VERSION 5.8 ;
BUSBITCHARS "[]" ;
DIVIDERCHAR "/" ;
UNITS
    DATABASE MICRONS 1000 ;
END UNITS

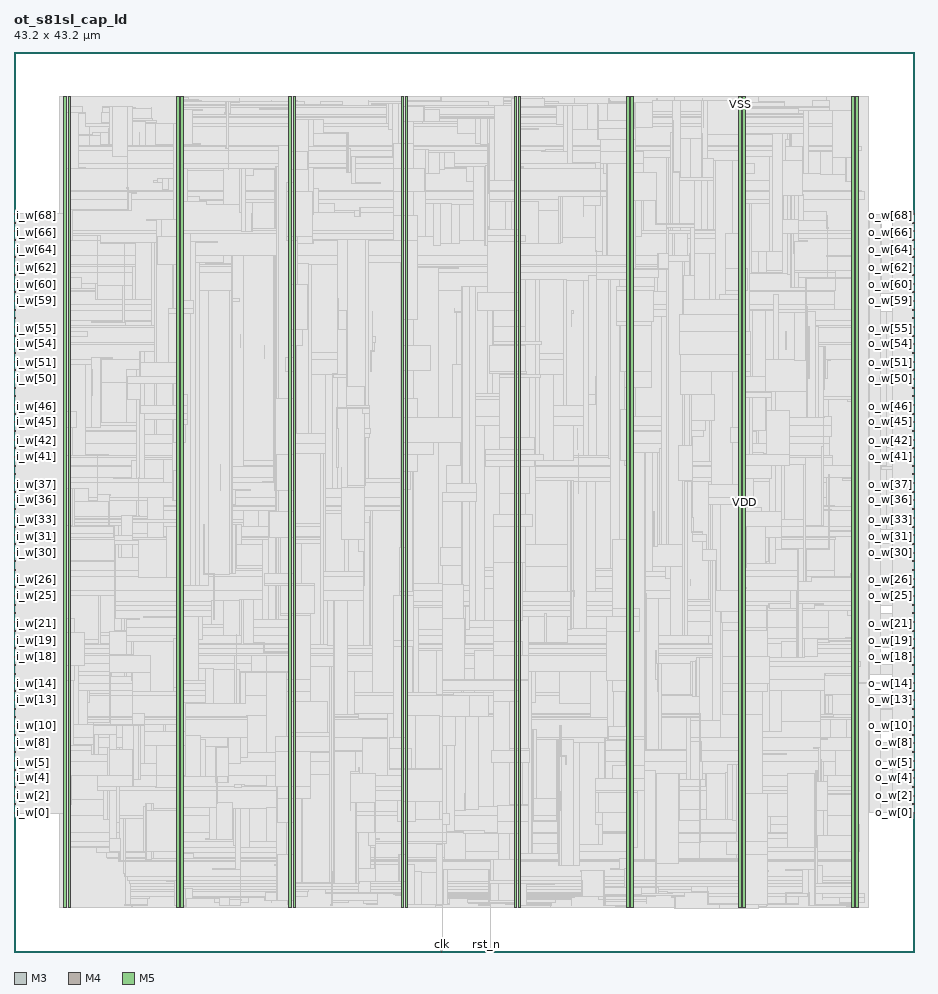
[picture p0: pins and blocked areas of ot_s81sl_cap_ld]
MACRO ot_s81sl_cap_ld
  FOREIGN ot_s81sl_cap_ld 0 0 ;
  CLASS BLOCK ;
  SIZE 43.2 BY 43.2 ;
  PIN clk
    DIRECTION INPUT ;
    USE SIGNAL ;
    PORT
      LAYER M3 ;
        RECT  20.52 0 20.538 0.038 ;
    END
  END clk
  PIN i_w[0]
    DIRECTION INPUT ;
    USE SIGNAL ;
    PORT
      LAYER M4 ;
        RECT  0 6.672 0.084 6.696 ;
    END
  END i_w[0]
  PIN i_w[10]
    DIRECTION INPUT ;
    USE SIGNAL ;
    PORT
      LAYER M4 ;
        RECT  0 10.848 0.084 10.872 ;
    END
  END i_w[10]
  PIN i_w[11]
    DIRECTION INPUT ;
    USE SIGNAL ;
    PORT
      LAYER M4 ;
        RECT  0 11.28 0.084 11.304 ;
    END
  END i_w[11]
  PIN i_w[12]
    DIRECTION INPUT ;
    USE SIGNAL ;
    PORT
      LAYER M4 ;
        RECT  0 11.664 0.084 11.688 ;
    END
  END i_w[12]
  PIN i_w[13]
    DIRECTION INPUT ;
    USE SIGNAL ;
    PORT
      LAYER M4 ;
        RECT  0 12.096 0.084 12.12 ;
    END
  END i_w[13]
  PIN i_w[14]
    DIRECTION INPUT ;
    USE SIGNAL ;
    PORT
      LAYER M4 ;
        RECT  0 12.528 0.084 12.552 ;
    END
  END i_w[14]
  PIN i_w[15]
    DIRECTION INPUT ;
    USE SIGNAL ;
    PORT
      LAYER M4 ;
        RECT  0 12.912 0.084 12.936 ;
    END
  END i_w[15]
  PIN i_w[16]
    DIRECTION INPUT ;
    USE SIGNAL ;
    PORT
      LAYER M4 ;
        RECT  0 13.344 0.084 13.368 ;
    END
  END i_w[16]
  PIN i_w[17]
    DIRECTION INPUT ;
    USE SIGNAL ;
    PORT
      LAYER M4 ;
        RECT  0 13.776 0.084 13.8 ;
    END
  END i_w[17]
  PIN i_w[18]
    DIRECTION INPUT ;
    USE SIGNAL ;
    PORT
      LAYER M4 ;
        RECT  0 14.16 0.084 14.184 ;
    END
  END i_w[18]
  PIN i_w[19]
    DIRECTION INPUT ;
    USE SIGNAL ;
    PORT
      LAYER M4 ;
        RECT  0 14.592 0.084 14.616 ;
    END
  END i_w[19]
  PIN i_w[1]
    DIRECTION INPUT ;
    USE SIGNAL ;
    PORT
      LAYER M4 ;
        RECT  0 7.104 0.084 7.128 ;
    END
  END i_w[1]
  PIN i_w[20]
    DIRECTION INPUT ;
    USE SIGNAL ;
    PORT
      LAYER M4 ;
        RECT  0 15.024 0.084 15.048 ;
    END
  END i_w[20]
  PIN i_w[21]
    DIRECTION INPUT ;
    USE SIGNAL ;
    PORT
      LAYER M4 ;
        RECT  0 15.408 0.084 15.432 ;
    END
  END i_w[21]
  PIN i_w[22]
    DIRECTION INPUT ;
    USE SIGNAL ;
    PORT
      LAYER M4 ;
        RECT  0 15.84 0.084 15.864 ;
    END
  END i_w[22]
  PIN i_w[23]
    DIRECTION INPUT ;
    USE SIGNAL ;
    PORT
      LAYER M4 ;
        RECT  0 16.272 0.084 16.296 ;
    END
  END i_w[23]
  PIN i_w[24]
    DIRECTION INPUT ;
    USE SIGNAL ;
    PORT
      LAYER M4 ;
        RECT  0 16.656 0.084 16.68 ;
    END
  END i_w[24]
  PIN i_w[25]
    DIRECTION INPUT ;
    USE SIGNAL ;
    PORT
      LAYER M4 ;
        RECT  0 17.088 0.084 17.112 ;
    END
  END i_w[25]
  PIN i_w[26]
    DIRECTION INPUT ;
    USE SIGNAL ;
    PORT
      LAYER M4 ;
        RECT  0 17.52 0.084 17.544 ;
    END
  END i_w[26]
  PIN i_w[27]
    DIRECTION INPUT ;
    USE SIGNAL ;
    PORT
      LAYER M4 ;
        RECT  0 17.904 0.084 17.928 ;
    END
  END i_w[27]
  PIN i_w[28]
    DIRECTION INPUT ;
    USE SIGNAL ;
    PORT
      LAYER M4 ;
        RECT  0 18.336 0.084 18.36 ;
    END
  END i_w[28]
  PIN i_w[29]
    DIRECTION INPUT ;
    USE SIGNAL ;
    PORT
      LAYER M4 ;
        RECT  0 18.768 0.084 18.792 ;
    END
  END i_w[29]
  PIN i_w[2]
    DIRECTION INPUT ;
    USE SIGNAL ;
    PORT
      LAYER M4 ;
        RECT  0 7.488 0.084 7.512 ;
    END
  END i_w[2]
  PIN i_w[30]
    DIRECTION INPUT ;
    USE SIGNAL ;
    PORT
      LAYER M4 ;
        RECT  0 19.152 0.084 19.176 ;
    END
  END i_w[30]
  PIN i_w[31]
    DIRECTION INPUT ;
    USE SIGNAL ;
    PORT
      LAYER M4 ;
        RECT  0 19.584 0.084 19.608 ;
    END
  END i_w[31]
  PIN i_w[32]
    DIRECTION INPUT ;
    USE SIGNAL ;
    PORT
      LAYER M4 ;
        RECT  0 20.016 0.084 20.04 ;
    END
  END i_w[32]
  PIN i_w[33]
    DIRECTION INPUT ;
    USE SIGNAL ;
    PORT
      LAYER M4 ;
        RECT  0 20.4 0.084 20.424 ;
    END
  END i_w[33]
  PIN i_w[34]
    DIRECTION INPUT ;
    USE SIGNAL ;
    PORT
      LAYER M4 ;
        RECT  0 20.832 0.084 20.856 ;
    END
  END i_w[34]
  PIN i_w[35]
    DIRECTION INPUT ;
    USE SIGNAL ;
    PORT
      LAYER M4 ;
        RECT  0 21.264 0.084 21.288 ;
    END
  END i_w[35]
  PIN i_w[36]
    DIRECTION INPUT ;
    USE SIGNAL ;
    PORT
      LAYER M4 ;
        RECT  0 21.696 0.084 21.72 ;
    END
  END i_w[36]
  PIN i_w[37]
    DIRECTION INPUT ;
    USE SIGNAL ;
    PORT
      LAYER M4 ;
        RECT  0 22.08 0.084 22.104 ;
    END
  END i_w[37]
  PIN i_w[38]
    DIRECTION INPUT ;
    USE SIGNAL ;
    PORT
      LAYER M4 ;
        RECT  0 22.512 0.084 22.536 ;
    END
  END i_w[38]
  PIN i_w[39]
    DIRECTION INPUT ;
    USE SIGNAL ;
    PORT
      LAYER M4 ;
        RECT  0 22.944 0.084 22.968 ;
    END
  END i_w[39]
  PIN i_w[3]
    DIRECTION INPUT ;
    USE SIGNAL ;
    PORT
      LAYER M4 ;
        RECT  0 7.92 0.084 7.944 ;
    END
  END i_w[3]
  PIN i_w[40]
    DIRECTION INPUT ;
    USE SIGNAL ;
    PORT
      LAYER M4 ;
        RECT  0 23.328 0.084 23.352 ;
    END
  END i_w[40]
  PIN i_w[41]
    DIRECTION INPUT ;
    USE SIGNAL ;
    PORT
      LAYER M4 ;
        RECT  0 23.76 0.084 23.784 ;
    END
  END i_w[41]
  PIN i_w[42]
    DIRECTION INPUT ;
    USE SIGNAL ;
    PORT
      LAYER M4 ;
        RECT  0 24.192 0.084 24.216 ;
    END
  END i_w[42]
  PIN i_w[43]
    DIRECTION INPUT ;
    USE SIGNAL ;
    PORT
      LAYER M4 ;
        RECT  0 24.576 0.084 24.6 ;
    END
  END i_w[43]
  PIN i_w[44]
    DIRECTION INPUT ;
    USE SIGNAL ;
    PORT
      LAYER M4 ;
        RECT  0 25.008 0.084 25.032 ;
    END
  END i_w[44]
  PIN i_w[45]
    DIRECTION INPUT ;
    USE SIGNAL ;
    PORT
      LAYER M4 ;
        RECT  0 25.44 0.084 25.464 ;
    END
  END i_w[45]
  PIN i_w[46]
    DIRECTION INPUT ;
    USE SIGNAL ;
    PORT
      LAYER M4 ;
        RECT  0 25.824 0.084 25.848 ;
    END
  END i_w[46]
  PIN i_w[47]
    DIRECTION INPUT ;
    USE SIGNAL ;
    PORT
      LAYER M4 ;
        RECT  0 26.256 0.084 26.28 ;
    END
  END i_w[47]
  PIN i_w[48]
    DIRECTION INPUT ;
    USE SIGNAL ;
    PORT
      LAYER M4 ;
        RECT  0 26.688 0.084 26.712 ;
    END
  END i_w[48]
  PIN i_w[49]
    DIRECTION INPUT ;
    USE SIGNAL ;
    PORT
      LAYER M4 ;
        RECT  0 27.072 0.084 27.096 ;
    END
  END i_w[49]
  PIN i_w[4]
    DIRECTION INPUT ;
    USE SIGNAL ;
    PORT
      LAYER M4 ;
        RECT  0 8.352 0.084 8.376 ;
    END
  END i_w[4]
  PIN i_w[50]
    DIRECTION INPUT ;
    USE SIGNAL ;
    PORT
      LAYER M4 ;
        RECT  0 27.504 0.084 27.528 ;
    END
  END i_w[50]
  PIN i_w[51]
    DIRECTION INPUT ;
    USE SIGNAL ;
    PORT
      LAYER M4 ;
        RECT  0 27.936 0.084 27.96 ;
    END
  END i_w[51]
  PIN i_w[52]
    DIRECTION INPUT ;
    USE SIGNAL ;
    PORT
      LAYER M4 ;
        RECT  0 28.32 0.084 28.344 ;
    END
  END i_w[52]
  PIN i_w[53]
    DIRECTION INPUT ;
    USE SIGNAL ;
    PORT
      LAYER M4 ;
        RECT  0 28.752 0.084 28.776 ;
    END
  END i_w[53]
  PIN i_w[54]
    DIRECTION INPUT ;
    USE SIGNAL ;
    PORT
      LAYER M4 ;
        RECT  0 29.184 0.084 29.208 ;
    END
  END i_w[54]
  PIN i_w[55]
    DIRECTION INPUT ;
    USE SIGNAL ;
    PORT
      LAYER M4 ;
        RECT  0 29.568 0.084 29.592 ;
    END
  END i_w[55]
  PIN i_w[56]
    DIRECTION INPUT ;
    USE SIGNAL ;
    PORT
      LAYER M4 ;
        RECT  0 30 0.084 30.024 ;
    END
  END i_w[56]
  PIN i_w[57]
    DIRECTION INPUT ;
    USE SIGNAL ;
    PORT
      LAYER M4 ;
        RECT  0 30.432 0.084 30.456 ;
    END
  END i_w[57]
  PIN i_w[58]
    DIRECTION INPUT ;
    USE SIGNAL ;
    PORT
      LAYER M4 ;
        RECT  0 30.816 0.084 30.84 ;
    END
  END i_w[58]
  PIN i_w[59]
    DIRECTION INPUT ;
    USE SIGNAL ;
    PORT
      LAYER M4 ;
        RECT  0 31.248 0.084 31.272 ;
    END
  END i_w[59]
  PIN i_w[5]
    DIRECTION INPUT ;
    USE SIGNAL ;
    PORT
      LAYER M4 ;
        RECT  0 8.736 0.084 8.76 ;
    END
  END i_w[5]
  PIN i_w[60]
    DIRECTION INPUT ;
    USE SIGNAL ;
    PORT
      LAYER M4 ;
        RECT  0 31.68 0.084 31.704 ;
    END
  END i_w[60]
  PIN i_w[61]
    DIRECTION INPUT ;
    USE SIGNAL ;
    PORT
      LAYER M4 ;
        RECT  0 32.064 0.084 32.088 ;
    END
  END i_w[61]
  PIN i_w[62]
    DIRECTION INPUT ;
    USE SIGNAL ;
    PORT
      LAYER M4 ;
        RECT  0 32.496 0.084 32.52 ;
    END
  END i_w[62]
  PIN i_w[63]
    DIRECTION INPUT ;
    USE SIGNAL ;
    PORT
      LAYER M4 ;
        RECT  0 32.928 0.084 32.952 ;
    END
  END i_w[63]
  PIN i_w[64]
    DIRECTION INPUT ;
    USE SIGNAL ;
    PORT
      LAYER M4 ;
        RECT  0 33.36 0.084 33.384 ;
    END
  END i_w[64]
  PIN i_w[65]
    DIRECTION INPUT ;
    USE SIGNAL ;
    PORT
      LAYER M4 ;
        RECT  0 33.744 0.084 33.768 ;
    END
  END i_w[65]
  PIN i_w[66]
    DIRECTION INPUT ;
    USE SIGNAL ;
    PORT
      LAYER M4 ;
        RECT  0 34.176 0.084 34.2 ;
    END
  END i_w[66]
  PIN i_w[67]
    DIRECTION INPUT ;
    USE SIGNAL ;
    PORT
      LAYER M4 ;
        RECT  0 34.608 0.084 34.632 ;
    END
  END i_w[67]
  PIN i_w[68]
    DIRECTION INPUT ;
    USE SIGNAL ;
    PORT
      LAYER M4 ;
        RECT  0 34.992 0.084 35.016 ;
    END
  END i_w[68]
  PIN i_w[69]
    DIRECTION INPUT ;
    USE SIGNAL ;
    PORT
      LAYER M4 ;
        RECT  0 35.424 0.084 35.448 ;
    END
  END i_w[69]
  PIN i_w[6]
    DIRECTION INPUT ;
    USE SIGNAL ;
    PORT
      LAYER M4 ;
        RECT  0 9.168 0.084 9.192 ;
    END
  END i_w[6]
  PIN i_w[7]
    DIRECTION INPUT ;
    USE SIGNAL ;
    PORT
      LAYER M4 ;
        RECT  0 9.6 0.084 9.624 ;
    END
  END i_w[7]
  PIN i_w[8]
    DIRECTION INPUT ;
    USE SIGNAL ;
    PORT
      LAYER M4 ;
        RECT  0 10.032 0.084 10.056 ;
    END
  END i_w[8]
  PIN i_w[9]
    DIRECTION INPUT ;
    USE SIGNAL ;
    PORT
      LAYER M4 ;
        RECT  0 10.416 0.084 10.44 ;
    END
  END i_w[9]
  PIN o_w[0]
    DIRECTION OUTPUT ;
    USE SIGNAL ;
    PORT
      LAYER M4 ;
        RECT  43.116 6.672 43.2 6.696 ;
    END
  END o_w[0]
  PIN o_w[10]
    DIRECTION OUTPUT ;
    USE SIGNAL ;
    PORT
      LAYER M4 ;
        RECT  43.116 10.848 43.2 10.872 ;
    END
  END o_w[10]
  PIN o_w[11]
    DIRECTION OUTPUT ;
    USE SIGNAL ;
    PORT
      LAYER M4 ;
        RECT  43.116 11.28 43.2 11.304 ;
    END
  END o_w[11]
  PIN o_w[12]
    DIRECTION OUTPUT ;
    USE SIGNAL ;
    PORT
      LAYER M4 ;
        RECT  43.116 11.664 43.2 11.688 ;
    END
  END o_w[12]
  PIN o_w[13]
    DIRECTION OUTPUT ;
    USE SIGNAL ;
    PORT
      LAYER M4 ;
        RECT  43.116 12.096 43.2 12.12 ;
    END
  END o_w[13]
  PIN o_w[14]
    DIRECTION OUTPUT ;
    USE SIGNAL ;
    PORT
      LAYER M4 ;
        RECT  43.116 12.528 43.2 12.552 ;
    END
  END o_w[14]
  PIN o_w[15]
    DIRECTION OUTPUT ;
    USE SIGNAL ;
    PORT
      LAYER M4 ;
        RECT  43.116 12.912 43.2 12.936 ;
    END
  END o_w[15]
  PIN o_w[16]
    DIRECTION OUTPUT ;
    USE SIGNAL ;
    PORT
      LAYER M4 ;
        RECT  43.116 13.344 43.2 13.368 ;
    END
  END o_w[16]
  PIN o_w[17]
    DIRECTION OUTPUT ;
    USE SIGNAL ;
    PORT
      LAYER M4 ;
        RECT  43.116 13.776 43.2 13.8 ;
    END
  END o_w[17]
  PIN o_w[18]
    DIRECTION OUTPUT ;
    USE SIGNAL ;
    PORT
      LAYER M4 ;
        RECT  43.116 14.16 43.2 14.184 ;
    END
  END o_w[18]
  PIN o_w[19]
    DIRECTION OUTPUT ;
    USE SIGNAL ;
    PORT
      LAYER M4 ;
        RECT  43.116 14.592 43.2 14.616 ;
    END
  END o_w[19]
  PIN o_w[1]
    DIRECTION OUTPUT ;
    USE SIGNAL ;
    PORT
      LAYER M4 ;
        RECT  43.116 7.104 43.2 7.128 ;
    END
  END o_w[1]
  PIN o_w[20]
    DIRECTION OUTPUT ;
    USE SIGNAL ;
    PORT
      LAYER M4 ;
        RECT  43.116 15.024 43.2 15.048 ;
    END
  END o_w[20]
  PIN o_w[21]
    DIRECTION OUTPUT ;
    USE SIGNAL ;
    PORT
      LAYER M4 ;
        RECT  43.116 15.408 43.2 15.432 ;
    END
  END o_w[21]
  PIN o_w[22]
    DIRECTION OUTPUT ;
    USE SIGNAL ;
    PORT
      LAYER M4 ;
        RECT  43.116 15.84 43.2 15.864 ;
    END
  END o_w[22]
  PIN o_w[23]
    DIRECTION OUTPUT ;
    USE SIGNAL ;
    PORT
      LAYER M4 ;
        RECT  43.116 16.272 43.2 16.296 ;
    END
  END o_w[23]
  PIN o_w[24]
    DIRECTION OUTPUT ;
    USE SIGNAL ;
    PORT
      LAYER M4 ;
        RECT  43.116 16.656 43.2 16.68 ;
    END
  END o_w[24]
  PIN o_w[25]
    DIRECTION OUTPUT ;
    USE SIGNAL ;
    PORT
      LAYER M4 ;
        RECT  43.116 17.088 43.2 17.112 ;
    END
  END o_w[25]
  PIN o_w[26]
    DIRECTION OUTPUT ;
    USE SIGNAL ;
    PORT
      LAYER M4 ;
        RECT  43.116 17.52 43.2 17.544 ;
    END
  END o_w[26]
  PIN o_w[27]
    DIRECTION OUTPUT ;
    USE SIGNAL ;
    PORT
      LAYER M4 ;
        RECT  43.116 17.904 43.2 17.928 ;
    END
  END o_w[27]
  PIN o_w[28]
    DIRECTION OUTPUT ;
    USE SIGNAL ;
    PORT
      LAYER M4 ;
        RECT  43.116 18.336 43.2 18.36 ;
    END
  END o_w[28]
  PIN o_w[29]
    DIRECTION OUTPUT ;
    USE SIGNAL ;
    PORT
      LAYER M4 ;
        RECT  43.116 18.768 43.2 18.792 ;
    END
  END o_w[29]
  PIN o_w[2]
    DIRECTION OUTPUT ;
    USE SIGNAL ;
    PORT
      LAYER M4 ;
        RECT  43.116 7.488 43.2 7.512 ;
    END
  END o_w[2]
  PIN o_w[30]
    DIRECTION OUTPUT ;
    USE SIGNAL ;
    PORT
      LAYER M4 ;
        RECT  43.116 19.152 43.2 19.176 ;
    END
  END o_w[30]
  PIN o_w[31]
    DIRECTION OUTPUT ;
    USE SIGNAL ;
    PORT
      LAYER M4 ;
        RECT  43.116 19.584 43.2 19.608 ;
    END
  END o_w[31]
  PIN o_w[32]
    DIRECTION OUTPUT ;
    USE SIGNAL ;
    PORT
      LAYER M4 ;
        RECT  43.116 20.016 43.2 20.04 ;
    END
  END o_w[32]
  PIN o_w[33]
    DIRECTION OUTPUT ;
    USE SIGNAL ;
    PORT
      LAYER M4 ;
        RECT  43.116 20.4 43.2 20.424 ;
    END
  END o_w[33]
  PIN o_w[34]
    DIRECTION OUTPUT ;
    USE SIGNAL ;
    PORT
      LAYER M4 ;
        RECT  43.116 20.832 43.2 20.856 ;
    END
  END o_w[34]
  PIN o_w[35]
    DIRECTION OUTPUT ;
    USE SIGNAL ;
    PORT
      LAYER M4 ;
        RECT  43.116 21.264 43.2 21.288 ;
    END
  END o_w[35]
  PIN o_w[36]
    DIRECTION OUTPUT ;
    USE SIGNAL ;
    PORT
      LAYER M4 ;
        RECT  43.116 21.696 43.2 21.72 ;
    END
  END o_w[36]
  PIN o_w[37]
    DIRECTION OUTPUT ;
    USE SIGNAL ;
    PORT
      LAYER M4 ;
        RECT  43.116 22.08 43.2 22.104 ;
    END
  END o_w[37]
  PIN o_w[38]
    DIRECTION OUTPUT ;
    USE SIGNAL ;
    PORT
      LAYER M4 ;
        RECT  43.116 22.512 43.2 22.536 ;
    END
  END o_w[38]
  PIN o_w[39]
    DIRECTION OUTPUT ;
    USE SIGNAL ;
    PORT
      LAYER M4 ;
        RECT  43.116 22.944 43.2 22.968 ;
    END
  END o_w[39]
  PIN o_w[3]
    DIRECTION OUTPUT ;
    USE SIGNAL ;
    PORT
      LAYER M4 ;
        RECT  43.116 7.92 43.2 7.944 ;
    END
  END o_w[3]
  PIN o_w[40]
    DIRECTION OUTPUT ;
    USE SIGNAL ;
    PORT
      LAYER M4 ;
        RECT  43.116 23.328 43.2 23.352 ;
    END
  END o_w[40]
  PIN o_w[41]
    DIRECTION OUTPUT ;
    USE SIGNAL ;
    PORT
      LAYER M4 ;
        RECT  43.116 23.76 43.2 23.784 ;
    END
  END o_w[41]
  PIN o_w[42]
    DIRECTION OUTPUT ;
    USE SIGNAL ;
    PORT
      LAYER M4 ;
        RECT  43.116 24.192 43.2 24.216 ;
    END
  END o_w[42]
  PIN o_w[43]
    DIRECTION OUTPUT ;
    USE SIGNAL ;
    PORT
      LAYER M4 ;
        RECT  43.116 24.576 43.2 24.6 ;
    END
  END o_w[43]
  PIN o_w[44]
    DIRECTION OUTPUT ;
    USE SIGNAL ;
    PORT
      LAYER M4 ;
        RECT  43.116 25.008 43.2 25.032 ;
    END
  END o_w[44]
  PIN o_w[45]
    DIRECTION OUTPUT ;
    USE SIGNAL ;
    PORT
      LAYER M4 ;
        RECT  43.116 25.44 43.2 25.464 ;
    END
  END o_w[45]
  PIN o_w[46]
    DIRECTION OUTPUT ;
    USE SIGNAL ;
    PORT
      LAYER M4 ;
        RECT  43.116 25.824 43.2 25.848 ;
    END
  END o_w[46]
  PIN o_w[47]
    DIRECTION OUTPUT ;
    USE SIGNAL ;
    PORT
      LAYER M4 ;
        RECT  43.116 26.256 43.2 26.28 ;
    END
  END o_w[47]
  PIN o_w[48]
    DIRECTION OUTPUT ;
    USE SIGNAL ;
    PORT
      LAYER M4 ;
        RECT  43.116 26.688 43.2 26.712 ;
    END
  END o_w[48]
  PIN o_w[49]
    DIRECTION OUTPUT ;
    USE SIGNAL ;
    PORT
      LAYER M4 ;
        RECT  43.116 27.072 43.2 27.096 ;
    END
  END o_w[49]
  PIN o_w[4]
    DIRECTION OUTPUT ;
    USE SIGNAL ;
    PORT
      LAYER M4 ;
        RECT  43.116 8.352 43.2 8.376 ;
    END
  END o_w[4]
  PIN o_w[50]
    DIRECTION OUTPUT ;
    USE SIGNAL ;
    PORT
      LAYER M4 ;
        RECT  43.116 27.504 43.2 27.528 ;
    END
  END o_w[50]
  PIN o_w[51]
    DIRECTION OUTPUT ;
    USE SIGNAL ;
    PORT
      LAYER M4 ;
        RECT  43.116 27.936 43.2 27.96 ;
    END
  END o_w[51]
  PIN o_w[52]
    DIRECTION OUTPUT ;
    USE SIGNAL ;
    PORT
      LAYER M4 ;
        RECT  43.116 28.32 43.2 28.344 ;
    END
  END o_w[52]
  PIN o_w[53]
    DIRECTION OUTPUT ;
    USE SIGNAL ;
    PORT
      LAYER M4 ;
        RECT  43.116 28.752 43.2 28.776 ;
    END
  END o_w[53]
  PIN o_w[54]
    DIRECTION OUTPUT ;
    USE SIGNAL ;
    PORT
      LAYER M4 ;
        RECT  43.116 29.184 43.2 29.208 ;
    END
  END o_w[54]
  PIN o_w[55]
    DIRECTION OUTPUT ;
    USE SIGNAL ;
    PORT
      LAYER M4 ;
        RECT  43.116 29.568 43.2 29.592 ;
    END
  END o_w[55]
  PIN o_w[56]
    DIRECTION OUTPUT ;
    USE SIGNAL ;
    PORT
      LAYER M4 ;
        RECT  43.116 30 43.2 30.024 ;
    END
  END o_w[56]
  PIN o_w[57]
    DIRECTION OUTPUT ;
    USE SIGNAL ;
    PORT
      LAYER M4 ;
        RECT  43.116 30.432 43.2 30.456 ;
    END
  END o_w[57]
  PIN o_w[58]
    DIRECTION OUTPUT ;
    USE SIGNAL ;
    PORT
      LAYER M4 ;
        RECT  43.116 30.816 43.2 30.84 ;
    END
  END o_w[58]
  PIN o_w[59]
    DIRECTION OUTPUT ;
    USE SIGNAL ;
    PORT
      LAYER M4 ;
        RECT  43.116 31.248 43.2 31.272 ;
    END
  END o_w[59]
  PIN o_w[5]
    DIRECTION OUTPUT ;
    USE SIGNAL ;
    PORT
      LAYER M4 ;
        RECT  43.116 8.736 43.2 8.76 ;
    END
  END o_w[5]
  PIN o_w[60]
    DIRECTION OUTPUT ;
    USE SIGNAL ;
    PORT
      LAYER M4 ;
        RECT  43.116 31.68 43.2 31.704 ;
    END
  END o_w[60]
  PIN o_w[61]
    DIRECTION OUTPUT ;
    USE SIGNAL ;
    PORT
      LAYER M4 ;
        RECT  43.116 32.064 43.2 32.088 ;
    END
  END o_w[61]
  PIN o_w[62]
    DIRECTION OUTPUT ;
    USE SIGNAL ;
    PORT
      LAYER M4 ;
        RECT  43.116 32.496 43.2 32.52 ;
    END
  END o_w[62]
  PIN o_w[63]
    DIRECTION OUTPUT ;
    USE SIGNAL ;
    PORT
      LAYER M4 ;
        RECT  43.116 32.928 43.2 32.952 ;
    END
  END o_w[63]
  PIN o_w[64]
    DIRECTION OUTPUT ;
    USE SIGNAL ;
    PORT
      LAYER M4 ;
        RECT  43.116 33.36 43.2 33.384 ;
    END
  END o_w[64]
  PIN o_w[65]
    DIRECTION OUTPUT ;
    USE SIGNAL ;
    PORT
      LAYER M4 ;
        RECT  43.116 33.744 43.2 33.768 ;
    END
  END o_w[65]
  PIN o_w[66]
    DIRECTION OUTPUT ;
    USE SIGNAL ;
    PORT
      LAYER M4 ;
        RECT  43.116 34.176 43.2 34.2 ;
    END
  END o_w[66]
  PIN o_w[67]
    DIRECTION OUTPUT ;
    USE SIGNAL ;
    PORT
      LAYER M4 ;
        RECT  43.116 34.608 43.2 34.632 ;
    END
  END o_w[67]
  PIN o_w[68]
    DIRECTION OUTPUT ;
    USE SIGNAL ;
    PORT
      LAYER M4 ;
        RECT  43.116 34.992 43.2 35.016 ;
    END
  END o_w[68]
  PIN o_w[69]
    DIRECTION OUTPUT ;
    USE SIGNAL ;
    PORT
      LAYER M4 ;
        RECT  43.116 35.424 43.2 35.448 ;
    END
  END o_w[69]
  PIN o_w[6]
    DIRECTION OUTPUT ;
    USE SIGNAL ;
    PORT
      LAYER M4 ;
        RECT  43.116 9.168 43.2 9.192 ;
    END
  END o_w[6]
  PIN o_w[7]
    DIRECTION OUTPUT ;
    USE SIGNAL ;
    PORT
      LAYER M4 ;
        RECT  43.116 9.6 43.2 9.624 ;
    END
  END o_w[7]
  PIN o_w[8]
    DIRECTION OUTPUT ;
    USE SIGNAL ;
    PORT
      LAYER M4 ;
        RECT  43.116 10.032 43.2 10.056 ;
    END
  END o_w[8]
  PIN o_w[9]
    DIRECTION OUTPUT ;
    USE SIGNAL ;
    PORT
      LAYER M4 ;
        RECT  43.116 10.416 43.2 10.44 ;
    END
  END o_w[9]
  PIN rst_n
    DIRECTION INPUT ;
    USE SIGNAL ;
    PORT
      LAYER M3 ;
        RECT  22.68 0 22.698 0.038 ;
    END
  END rst_n
  PIN VDD
    DIRECTION INOUT ;
    USE POWER ;
    PORT
      LAYER M5 ;
        RECT  40.392 2.151 40.512 41.049 ;
        RECT  34.992 2.151 35.112 41.049 ;
        RECT  29.592 2.151 29.712 41.049 ;
        RECT  24.192 2.151 24.312 41.049 ;
        RECT  18.792 2.151 18.912 41.049 ;
        RECT  13.392 2.151 13.512 41.049 ;
        RECT  7.992 2.151 8.112 41.049 ;
        RECT  2.592 2.151 2.712 41.049 ;
    END
  END VDD
  PIN VSS
    DIRECTION INOUT ;
    USE GROUND ;
    PORT
      LAYER M5 ;
        RECT  40.2 2.137 40.32 41.063 ;
        RECT  34.8 2.137 34.92 41.063 ;
        RECT  29.4 2.137 29.52 41.063 ;
        RECT  24 2.137 24.12 41.063 ;
        RECT  18.6 2.137 18.72 41.063 ;
        RECT  13.2 2.137 13.32 41.063 ;
        RECT  7.8 2.137 7.92 41.063 ;
        RECT  2.4 2.137 2.52 41.063 ;
    END
  END VSS
  OBS
    LAYER RVTN ;
     RECT  2.16 2.16 41.04 2.295 ;
     RECT  2.16 2.565 41.04 2.835 ;
     RECT  2.16 3.105 41.04 3.375 ;
     RECT  2.16 3.645 41.04 3.915 ;
     RECT  2.16 4.185 41.04 4.455 ;
     RECT  2.16 4.725 41.04 4.995 ;
     RECT  2.16 5.265 41.04 5.535 ;
     RECT  2.16 5.805 41.04 6.075 ;
     RECT  2.16 6.345 41.04 6.615 ;
     RECT  2.16 6.885 41.04 7.155 ;
     RECT  2.16 7.425 41.04 7.695 ;
     RECT  2.16 7.965 41.04 8.235 ;
     RECT  2.16 8.505 41.04 8.775 ;
     RECT  2.16 9.045 41.04 9.315 ;
     RECT  2.16 9.585 41.04 9.855 ;
     RECT  2.16 10.125 41.04 10.395 ;
     RECT  2.16 10.665 41.04 10.935 ;
     RECT  2.16 11.205 41.04 11.475 ;
     RECT  2.16 11.745 41.04 12.015 ;
     RECT  2.16 12.285 41.04 12.555 ;
     RECT  2.16 12.825 41.04 13.095 ;
     RECT  2.16 13.365 41.04 13.635 ;
     RECT  2.16 13.905 41.04 14.175 ;
     RECT  2.16 14.445 41.04 14.715 ;
     RECT  2.16 14.985 41.04 15.255 ;
     RECT  2.16 15.525 41.04 15.795 ;
     RECT  2.16 16.065 41.04 16.335 ;
     RECT  2.16 16.605 41.04 16.875 ;
     RECT  2.16 17.145 41.04 17.415 ;
     RECT  2.16 17.685 41.04 17.955 ;
     RECT  2.16 18.225 41.04 18.495 ;
     RECT  2.16 18.765 41.04 19.035 ;
     RECT  2.16 19.305 41.04 19.575 ;
     RECT  2.16 19.845 41.04 20.115 ;
     RECT  2.16 20.385 41.04 20.655 ;
     RECT  2.16 20.925 41.04 21.195 ;
     RECT  2.16 21.465 41.04 21.735 ;
     RECT  2.16 22.005 41.04 22.275 ;
     RECT  2.16 22.545 41.04 22.815 ;
     RECT  2.16 23.085 41.04 23.355 ;
     RECT  2.16 23.625 41.04 23.895 ;
     RECT  2.16 24.165 41.04 24.435 ;
     RECT  2.16 24.705 41.04 24.975 ;
     RECT  2.16 25.245 41.04 25.515 ;
     RECT  2.16 25.785 41.04 26.055 ;
     RECT  2.16 26.325 41.04 26.595 ;
     RECT  2.16 26.865 41.04 27.135 ;
     RECT  2.16 27.405 41.04 27.675 ;
     RECT  2.16 27.945 41.04 28.215 ;
     RECT  2.16 28.485 41.04 28.755 ;
     RECT  2.16 29.025 41.04 29.295 ;
     RECT  2.16 29.565 41.04 29.835 ;
     RECT  2.16 30.105 41.04 30.375 ;
     RECT  2.16 30.645 41.04 30.915 ;
     RECT  2.16 31.185 41.04 31.455 ;
     RECT  2.16 31.725 41.04 31.995 ;
     RECT  2.16 32.265 41.04 32.535 ;
     RECT  2.16 32.805 41.04 33.075 ;
     RECT  2.16 33.345 41.04 33.615 ;
     RECT  2.16 33.885 41.04 34.155 ;
     RECT  2.16 34.425 41.04 34.695 ;
     RECT  2.16 34.965 41.04 35.235 ;
     RECT  2.16 35.505 41.04 35.775 ;
     RECT  2.16 36.045 41.04 36.315 ;
     RECT  2.16 36.585 41.04 36.855 ;
     RECT  2.16 37.125 41.04 37.395 ;
     RECT  2.16 37.665 41.04 37.935 ;
     RECT  2.16 38.205 41.04 38.475 ;
     RECT  2.16 38.745 41.04 39.015 ;
     RECT  2.16 39.285 41.04 39.555 ;
     RECT  2.16 39.825 41.04 40.095 ;
     RECT  2.16 40.365 41.04 40.635 ;
     RECT  2.16 40.905 41.04 41.04 ;
    LAYER RVTP ;
     RECT  2.16 2.295 41.04 2.565 ;
     RECT  2.16 2.835 41.04 3.105 ;
     RECT  2.16 3.375 41.04 3.645 ;
     RECT  2.16 3.915 41.04 4.185 ;
     RECT  2.16 4.455 41.04 4.725 ;
     RECT  2.16 4.995 41.04 5.265 ;
     RECT  2.16 5.535 41.04 5.805 ;
     RECT  2.16 6.075 41.04 6.345 ;
     RECT  2.16 6.615 41.04 6.885 ;
     RECT  2.16 7.155 41.04 7.425 ;
     RECT  2.16 7.695 41.04 7.965 ;
     RECT  2.16 8.235 41.04 8.505 ;
     RECT  2.16 8.775 41.04 9.045 ;
     RECT  2.16 9.315 41.04 9.585 ;
     RECT  2.16 9.855 41.04 10.125 ;
     RECT  2.16 10.395 41.04 10.665 ;
     RECT  2.16 10.935 41.04 11.205 ;
     RECT  2.16 11.475 41.04 11.745 ;
     RECT  2.16 12.015 41.04 12.285 ;
     RECT  2.16 12.555 41.04 12.825 ;
     RECT  2.16 13.095 41.04 13.365 ;
     RECT  2.16 13.635 41.04 13.905 ;
     RECT  2.16 14.175 41.04 14.445 ;
     RECT  2.16 14.715 41.04 14.985 ;
     RECT  2.16 15.255 41.04 15.525 ;
     RECT  2.16 15.795 41.04 16.065 ;
     RECT  2.16 16.335 41.04 16.605 ;
     RECT  2.16 16.875 41.04 17.145 ;
     RECT  2.16 17.415 41.04 17.685 ;
     RECT  2.16 17.955 41.04 18.225 ;
     RECT  2.16 18.495 41.04 18.765 ;
     RECT  2.16 19.035 41.04 19.305 ;
     RECT  2.16 19.575 41.04 19.845 ;
     RECT  2.16 20.115 41.04 20.385 ;
     RECT  2.16 20.655 41.04 20.925 ;
     RECT  2.16 21.195 41.04 21.465 ;
     RECT  2.16 21.735 41.04 22.005 ;
     RECT  2.16 22.275 41.04 22.545 ;
     RECT  2.16 22.815 41.04 23.085 ;
     RECT  2.16 23.355 41.04 23.625 ;
     RECT  2.16 23.895 41.04 24.165 ;
     RECT  2.16 24.435 41.04 24.705 ;
     RECT  2.16 24.975 41.04 25.245 ;
     RECT  2.16 25.515 41.04 25.785 ;
     RECT  2.16 26.055 41.04 26.325 ;
     RECT  2.16 26.595 41.04 26.865 ;
     RECT  2.16 27.135 41.04 27.405 ;
     RECT  2.16 27.675 41.04 27.945 ;
     RECT  2.16 28.215 41.04 28.485 ;
     RECT  2.16 28.755 41.04 29.025 ;
     RECT  2.16 29.295 41.04 29.565 ;
     RECT  2.16 29.835 41.04 30.105 ;
     RECT  2.16 30.375 41.04 30.645 ;
     RECT  2.16 30.915 41.04 31.185 ;
     RECT  2.16 31.455 41.04 31.725 ;
     RECT  2.16 31.995 41.04 32.265 ;
     RECT  2.16 32.535 41.04 32.805 ;
     RECT  2.16 33.075 41.04 33.345 ;
     RECT  2.16 33.615 41.04 33.885 ;
     RECT  2.16 34.155 41.04 34.425 ;
     RECT  2.16 34.695 41.04 34.965 ;
     RECT  2.16 35.235 41.04 35.505 ;
     RECT  2.16 35.775 41.04 36.045 ;
     RECT  2.16 36.315 41.04 36.585 ;
     RECT  2.16 36.855 41.04 37.125 ;
     RECT  2.16 37.395 41.04 37.665 ;
     RECT  2.16 37.935 41.04 38.205 ;
     RECT  2.16 38.475 41.04 38.745 ;
     RECT  2.16 39.015 41.04 39.285 ;
     RECT  2.16 39.555 41.04 39.825 ;
     RECT  2.16 40.095 41.04 40.365 ;
     RECT  2.16 40.635 41.04 40.905 ;
    LAYER M1 ;
     RECT  2.16 2.151 41.04 41.049 ;
    LAYER M2 ;
     RECT  0.103 12.528 2.16 12.546 ;
     RECT  0.103 17.082 2.16 17.1 ;
     RECT  0.103 24.48 2.16 24.498 ;
     RECT  0.103 32.472 2.16 32.49 ;
     RECT  22.675 0.036 22.883 0.054 ;
     RECT  2.16 2.151 31.711 41.049 ;
     RECT  31.711 2.106 35.735 41.049 ;
     RECT  35.735 2.151 41.04 41.049 ;
     RECT  41.04 6.696 41.063 35.424 ;
     RECT  41.063 6.696 41.603 12.384 ;
     RECT  41.063 13.338 41.603 35.424 ;
     RECT  41.603 18.126 41.639 18.684 ;
     RECT  41.603 31.626 41.639 35.424 ;
     RECT  41.603 20.286 41.891 30.744 ;
     RECT  41.603 6.696 42.179 8.766 ;
     RECT  41.603 9.756 42.179 9.774 ;
     RECT  41.603 10.566 42.179 12.384 ;
     RECT  41.603 13.338 42.179 13.824 ;
     RECT  41.603 14.616 42.179 16.254 ;
     RECT  41.639 18.126 42.179 18.144 ;
     RECT  41.891 20.286 42.179 23.814 ;
     RECT  41.891 24.606 42.179 30.744 ;
     RECT  41.639 31.626 42.179 34.344 ;
     RECT  41.639 35.136 42.179 35.424 ;
     RECT  42.179 11.916 42.215 12.384 ;
     RECT  42.179 30.726 42.215 30.744 ;
     RECT  42.215 12.366 43.115 12.384 ;
     RECT  42.179 15.336 43.115 15.354 ;
     RECT  41.603 17.046 43.115 17.064 ;
     RECT  42.179 26.226 43.115 26.244 ;
     RECT  42.179 27.756 43.115 27.774 ;
     RECT  42.179 32.436 43.115 32.454 ;
     RECT  42.179 34.326 43.115 34.344 ;
    LAYER M3 ;
     RECT  22.68 0.012 22.698 0.031 ;
     RECT  22.68 0.031 22.878 0.059 ;
     RECT  20.52 0.012 20.538 0.125 ;
     RECT  7.815 2.143 7.905 2.191 ;
     RECT  29.415 2.143 29.505 2.191 ;
     RECT  35.712 2.101 35.73 2.191 ;
     RECT  40.215 2.143 40.305 2.191 ;
     RECT  5.652 2.191 5.67 2.227 ;
     RECT  7.815 2.191 8.298 2.227 ;
     RECT  20.232 2.191 20.25 2.227 ;
     RECT  28.872 2.191 29.505 2.227 ;
     RECT  5.652 2.227 6.39 2.251 ;
     RECT  22.86 0.059 22.878 2.251 ;
     RECT  24.015 2.143 24.105 2.251 ;
     RECT  25.74 2.191 25.758 2.251 ;
     RECT  39.96 2.191 40.305 2.251 ;
     RECT  9.864 2.227 9.882 2.263 ;
     RECT  20.232 2.227 20.538 2.263 ;
     RECT  24.015 2.251 24.57 2.263 ;
     RECT  25.74 2.251 25.794 2.263 ;
     RECT  5.472 2.251 6.39 2.291 ;
     RECT  9.864 2.263 10.278 2.299 ;
     RECT  13.215 2.143 13.305 2.299 ;
     RECT  18.615 2.143 18.705 2.299 ;
     RECT  19.836 2.263 20.538 2.299 ;
     RECT  24.015 2.263 25.794 2.299 ;
     RECT  33.84 2.101 33.858 2.299 ;
     RECT  34.815 2.143 34.905 2.299 ;
     RECT  35.712 2.191 36.126 2.299 ;
     RECT  37.296 2.263 37.314 2.299 ;
     RECT  16.92 2.263 17.442 2.335 ;
     RECT  22.32 2.251 22.878 2.335 ;
     RECT  23.616 2.299 25.794 2.335 ;
     RECT  33.3 2.299 33.858 2.335 ;
     RECT  34.596 2.299 34.905 2.335 ;
     RECT  35.712 2.299 37.674 2.335 ;
     RECT  39.6 2.251 40.305 2.335 ;
     RECT  9.864 2.299 10.89 2.371 ;
     RECT  15.264 2.227 15.282 2.371 ;
     RECT  21.816 2.335 25.794 2.371 ;
     RECT  39.6 2.335 40.374 2.371 ;
     RECT  2.415 2.143 2.505 2.413 ;
     RECT  13.14 2.299 13.305 2.413 ;
     RECT  28.332 2.227 29.505 2.413 ;
     RECT  30.348 2.335 30.366 2.413 ;
     RECT  15.264 2.371 16.038 2.461 ;
     RECT  16.776 2.335 17.442 2.461 ;
     RECT  12.348 2.371 12.366 2.491 ;
     RECT  21.78 2.371 25.974 2.497 ;
     RECT  26.748 2.227 26.766 2.497 ;
     RECT  28.332 2.413 30.366 2.533 ;
     RECT  5.58 2.291 6.39 2.569 ;
     RECT  18.615 2.299 20.898 2.569 ;
     RECT  21.78 2.497 26.766 2.569 ;
     RECT  7.704 2.227 8.298 2.605 ;
     RECT  9.648 2.371 11.25 2.605 ;
     RECT  12.024 2.491 12.366 2.605 ;
     RECT  18.615 2.569 26.766 2.605 ;
     RECT  31.716 2.101 31.734 2.605 ;
     RECT  38.808 2.533 38.826 2.605 ;
     RECT  39.6 2.371 40.842 2.605 ;
     RECT  5.58 2.569 6.498 2.641 ;
     RECT  7.704 2.605 8.55 2.641 ;
     RECT  9.648 2.605 12.366 2.641 ;
     RECT  13.14 2.413 13.497 2.641 ;
     RECT  18.615 2.605 26.91 2.641 ;
     RECT  28.08 2.533 30.366 2.641 ;
     RECT  31.572 2.605 31.734 2.641 ;
     RECT  33.3 2.335 37.674 2.641 ;
     RECT  18.615 2.641 27.342 2.731 ;
     RECT  28.08 2.641 30.798 2.731 ;
     RECT  31.572 2.641 32.166 2.731 ;
     RECT  18.324 2.731 27.342 2.767 ;
     RECT  38.808 2.605 40.842 2.795 ;
     RECT  15.264 2.461 17.442 2.803 ;
     RECT  18.216 2.767 27.342 2.803 ;
     RECT  33.3 2.641 38.07 2.827 ;
     RECT  38.808 2.795 40.497 2.827 ;
     RECT  14.94 2.803 27.342 2.875 ;
     RECT  28.08 2.731 32.166 2.875 ;
     RECT  5.58 2.641 14.094 2.911 ;
     RECT  5.58 2.911 14.13 3.001 ;
     RECT  14.94 2.875 32.526 3.001 ;
     RECT  5.58 3.001 32.526 3.145 ;
     RECT  33.3 2.827 40.497 3.145 ;
     RECT  5.58 3.145 40.497 3.307 ;
     RECT  5.544 3.307 40.497 3.451 ;
     RECT  5.436 3.451 40.497 3.613 ;
     RECT  5.292 3.613 40.497 4.363 ;
     RECT  5.004 4.363 40.497 4.415 ;
     RECT  14.94 4.415 40.497 4.451 ;
     RECT  5.004 4.415 14.166 4.495 ;
     RECT  4.464 4.495 14.166 4.531 ;
     RECT  14.94 4.451 20.682 4.541 ;
     RECT  4.428 4.531 14.166 4.765 ;
     RECT  21.672 4.451 40.497 4.801 ;
     RECT  2.415 2.413 2.697 5.035 ;
     RECT  3.96 4.765 14.166 5.035 ;
     RECT  15.156 4.541 20.682 5.197 ;
     RECT  2.415 5.035 14.166 5.305 ;
     RECT  15.156 5.197 20.754 5.305 ;
     RECT  21.672 4.801 40.59 5.701 ;
     RECT  2.415 5.305 20.754 5.737 ;
     RECT  21.6 5.701 40.59 5.737 ;
     RECT  2.415 5.737 40.59 5.741 ;
     RECT  36.324 5.741 40.59 6.143 ;
     RECT  2.415 5.741 35.442 6.547 ;
     RECT  36.324 6.143 40.497 6.547 ;
     RECT  0.108 7.483 0.126 7.661 ;
     RECT  2.415 6.547 40.497 7.735 ;
     RECT  2.304 7.735 40.497 7.949 ;
     RECT  2.415 7.949 40.497 8.465 ;
     RECT  42.156 6.667 42.174 8.771 ;
     RECT  2.415 8.465 39.438 9.163 ;
     RECT  41.58 9.163 41.598 9.239 ;
     RECT  2.304 9.163 39.438 9.653 ;
     RECT  2.415 9.653 39.438 9.661 ;
     RECT  40.215 8.465 40.497 9.661 ;
     RECT  42.156 9.595 42.174 10.021 ;
     RECT  41.58 10.021 42.174 10.061 ;
     RECT  2.415 9.661 40.497 10.319 ;
     RECT  2.415 10.319 39.186 11.173 ;
     RECT  39.96 10.319 40.497 11.173 ;
     RECT  2.415 11.173 40.497 11.273 ;
     RECT  2.415 11.273 39.33 11.309 ;
     RECT  22.788 11.309 39.33 11.399 ;
     RECT  22.788 11.399 39.258 11.453 ;
     RECT  42.156 10.061 42.174 11.659 ;
     RECT  41.58 11.659 42.174 11.705 ;
     RECT  42.192 11.911 42.21 12.125 ;
     RECT  2.415 11.309 21.87 12.289 ;
     RECT  22.788 11.453 39.114 12.289 ;
     RECT  2.415 12.289 39.114 12.325 ;
     RECT  43.092 12.361 43.11 12.557 ;
     RECT  0.108 10.843 0.126 12.56 ;
     RECT  2.415 12.325 39.366 12.56 ;
     RECT  40.215 11.273 40.497 12.901 ;
     RECT  2.415 12.56 35.154 12.907 ;
     RECT  40.215 12.901 41.058 12.941 ;
     RECT  35.928 12.56 39.366 13.063 ;
     RECT  40.215 12.941 40.497 13.063 ;
     RECT  2.304 12.907 35.154 13.289 ;
     RECT  2.304 13.289 35.097 13.469 ;
     RECT  35.928 13.063 40.497 13.711 ;
     RECT  42.156 13.333 42.174 13.829 ;
     RECT  2.304 13.469 11.394 13.865 ;
     RECT  35.928 13.711 40.626 13.937 ;
     RECT  41.58 14.071 41.598 14.189 ;
     RECT  2.415 13.865 11.394 14.251 ;
     RECT  12.132 13.469 35.097 14.251 ;
     RECT  2.415 14.251 35.19 14.341 ;
     RECT  35.928 13.937 40.497 14.341 ;
     RECT  2.415 14.341 40.497 14.587 ;
     RECT  2.304 14.587 40.497 14.747 ;
     RECT  2.304 14.747 33.57 14.813 ;
     RECT  34.38 14.747 40.497 15.053 ;
     RECT  39.924 15.053 40.497 15.089 ;
     RECT  42.156 14.587 42.174 15.089 ;
     RECT  2.304 14.813 33.318 15.215 ;
     RECT  43.092 15.331 43.11 15.437 ;
     RECT  0.108 15.403 0.126 15.533 ;
     RECT  2.415 15.215 33.318 15.565 ;
     RECT  34.38 15.053 39.114 15.565 ;
     RECT  40.176 15.089 40.497 16.141 ;
     RECT  42.156 15.835 42.174 16.301 ;
     RECT  2.415 15.565 39.114 16.411 ;
     RECT  40.032 16.141 40.497 16.411 ;
     RECT  2.415 16.411 40.497 16.651 ;
     RECT  2.304 16.651 40.497 16.835 ;
     RECT  0.108 17.077 0.126 17.117 ;
     RECT  43.092 17.041 43.11 17.117 ;
     RECT  2.376 16.835 40.497 17.339 ;
     RECT  41.58 16.651 41.598 17.609 ;
     RECT  2.415 17.339 40.497 18.032 ;
     RECT  40.14 18.032 40.497 18.149 ;
     RECT  42.156 17.899 42.174 18.149 ;
     RECT  2.415 18.032 39.366 18.331 ;
     RECT  41.58 18.331 41.634 18.419 ;
     RECT  41.616 18.419 41.634 18.797 ;
     RECT  41.58 19.147 41.598 19.616 ;
     RECT  2.304 18.331 39.366 19.813 ;
     RECT  2.304 19.813 39.438 19.877 ;
     RECT  7.164 19.877 39.438 19.921 ;
     RECT  40.215 18.149 40.497 19.921 ;
     RECT  2.304 19.877 6.39 20.075 ;
     RECT  7.164 19.921 40.497 20.417 ;
     RECT  2.34 20.075 6.39 20.623 ;
     RECT  7.164 20.417 10.998 20.623 ;
     RECT  2.34 20.623 10.998 20.759 ;
     RECT  2.34 20.759 6.39 20.827 ;
     RECT  2.304 20.827 6.39 20.885 ;
     RECT  7.164 20.759 10.998 21.199 ;
     RECT  11.736 20.417 40.497 21.199 ;
     RECT  7.164 21.199 40.497 21.389 ;
     RECT  7.164 21.389 39.402 21.425 ;
     RECT  0.108 21.259 0.126 21.437 ;
     RECT  2.34 20.885 6.39 21.667 ;
     RECT  2.304 21.667 6.39 21.811 ;
     RECT  7.164 21.425 39.006 21.811 ;
     RECT  2.304 21.811 39.006 22.541 ;
     RECT  40.215 21.389 40.497 22.621 ;
     RECT  39.78 22.621 40.497 22.739 ;
     RECT  2.415 22.541 39.006 22.795 ;
     RECT  42.156 20.011 42.174 23.161 ;
     RECT  2.415 22.795 39.366 23.287 ;
     RECT  2.412 23.287 39.366 23.357 ;
     RECT  41.616 23.161 42.174 23.357 ;
     RECT  40.176 22.739 40.497 23.585 ;
     RECT  2.412 23.357 39.294 23.755 ;
     RECT  2.304 23.755 39.294 23.819 ;
     RECT  42.156 23.357 42.174 23.819 ;
     RECT  2.304 23.819 39.15 23.855 ;
     RECT  41.868 24.187 41.886 24.269 ;
     RECT  2.415 23.855 39.15 24.431 ;
     RECT  0.108 24.475 0.126 24.605 ;
     RECT  36.396 24.431 39.15 24.745 ;
     RECT  2.415 24.431 35.658 25.003 ;
     RECT  2.34 25.003 35.658 25.043 ;
     RECT  2.415 25.043 35.658 25.249 ;
     RECT  36.396 24.745 39.258 25.249 ;
     RECT  2.415 25.249 39.258 25.709 ;
     RECT  43.092 26.221 43.11 26.285 ;
     RECT  40.215 23.585 40.497 26.401 ;
     RECT  2.415 25.709 39.078 26.527 ;
     RECT  40.032 26.401 40.497 26.527 ;
     RECT  2.415 26.527 40.497 26.683 ;
     RECT  42.156 24.571 42.174 27.101 ;
     RECT  41.544 27.499 41.562 27.671 ;
     RECT  43.092 27.751 43.11 27.965 ;
     RECT  2.304 26.683 40.497 28.445 ;
     RECT  2.376 28.445 40.497 29.179 ;
     RECT  2.304 29.179 40.497 29.255 ;
     RECT  2.376 29.255 40.497 29.995 ;
     RECT  2.304 29.995 40.497 30.065 ;
     RECT  2.376 30.065 40.497 30.335 ;
     RECT  42.156 28.315 42.174 30.479 ;
     RECT  2.376 30.335 24.39 30.811 ;
     RECT  25.128 30.335 40.497 30.839 ;
     RECT  42.192 30.721 42.21 30.845 ;
     RECT  2.304 30.811 24.39 31.081 ;
     RECT  25.128 30.839 39.366 31.081 ;
     RECT  41.58 31.243 41.598 31.289 ;
     RECT  2.304 31.081 39.366 31.709 ;
     RECT  2.415 31.709 39.366 31.765 ;
     RECT  42.156 31.621 42.174 32.189 ;
     RECT  0.108 31.963 0.126 32.525 ;
     RECT  43.092 32.431 43.11 32.525 ;
     RECT  2.415 31.765 39.438 32.639 ;
     RECT  36.108 32.639 39.438 32.701 ;
     RECT  40.215 30.839 40.497 32.701 ;
     RECT  2.415 32.639 35.37 32.923 ;
     RECT  2.304 32.923 35.37 32.999 ;
     RECT  2.304 32.999 35.334 33.413 ;
     RECT  42.156 32.923 42.174 34.079 ;
     RECT  32.328 33.413 35.334 34.231 ;
     RECT  36.108 32.701 40.497 34.231 ;
     RECT  43.092 34.171 43.11 34.349 ;
     RECT  2.304 33.413 31.59 34.465 ;
     RECT  32.328 34.231 40.497 34.465 ;
     RECT  2.304 34.465 40.497 34.637 ;
     RECT  41.616 34.591 41.634 34.637 ;
     RECT  42.156 34.987 42.174 35.453 ;
     RECT  2.415 34.637 40.497 36.121 ;
     RECT  2.415 36.121 40.842 36.509 ;
     RECT  2.415 36.509 40.698 36.545 ;
     RECT  2.415 36.545 40.497 37.627 ;
     RECT  2.376 37.627 40.497 37.859 ;
     RECT  2.415 37.859 40.497 38.479 ;
     RECT  2.415 38.479 40.662 38.669 ;
     RECT  2.415 38.669 40.554 38.705 ;
     RECT  3.6 38.705 40.497 39.631 ;
     RECT  3.42 39.631 40.497 39.749 ;
     RECT  4.212 39.749 6.93 39.773 ;
     RECT  4.212 39.773 6.822 39.821 ;
     RECT  5.652 39.821 6.822 39.893 ;
     RECT  5.652 39.893 6.642 40.019 ;
     RECT  7.776 39.749 40.497 40.055 ;
     RECT  7.815 40.055 39.294 40.091 ;
     RECT  7.815 40.091 39.222 40.199 ;
     RECT  2.415 38.705 2.697 40.267 ;
     RECT  3.42 39.749 3.438 40.267 ;
     RECT  2.415 40.267 3.438 40.289 ;
     RECT  4.212 39.821 4.914 40.289 ;
     RECT  40.14 40.055 40.497 40.325 ;
     RECT  5.652 40.019 6.606 40.469 ;
     RECT  4.248 40.289 4.914 40.559 ;
     RECT  5.652 40.469 5.814 40.559 ;
     RECT  6.588 40.469 6.606 40.559 ;
     RECT  7.815 40.199 39.15 40.559 ;
     RECT  2.415 40.289 3.294 40.595 ;
     RECT  4.248 40.559 4.266 40.595 ;
     RECT  5.652 40.559 5.67 40.595 ;
     RECT  33.012 40.559 39.15 40.595 ;
     RECT  7.815 40.559 27.558 40.631 ;
     RECT  16.992 40.631 27.558 40.637 ;
     RECT  28.548 40.559 32.238 40.637 ;
     RECT  7.815 40.631 15.75 40.667 ;
     RECT  23.508 40.637 27.558 40.739 ;
     RECT  2.415 40.595 2.697 40.787 ;
     RECT  28.548 40.637 29.697 40.787 ;
     RECT  33.012 40.595 36.99 40.787 ;
     RECT  40.215 40.325 40.497 40.787 ;
     RECT  7.815 40.667 13.95 40.829 ;
     RECT  14.724 40.667 15.75 40.829 ;
     RECT  16.992 40.637 22.77 40.829 ;
     RECT  23.508 40.739 26.118 40.829 ;
     RECT  28.548 40.787 29.505 40.829 ;
     RECT  30.672 40.637 32.238 40.829 ;
     RECT  33.012 40.787 34.905 40.829 ;
     RECT  35.712 40.787 36.99 40.829 ;
     RECT  10.152 40.829 10.818 40.835 ;
     RECT  7.815 40.829 9.018 40.865 ;
     RECT  12.348 40.829 12.366 40.865 ;
     RECT  13.215 40.829 13.59 40.865 ;
     RECT  16.992 40.829 17.01 40.865 ;
     RECT  18.615 40.829 20.502 40.865 ;
     RECT  23.508 40.829 25.434 40.865 ;
     RECT  28.548 40.829 28.638 40.865 ;
     RECT  35.712 40.829 35.73 40.865 ;
     RECT  38.304 40.595 39.15 40.865 ;
     RECT  30.672 40.829 30.87 40.877 ;
     RECT  31.932 40.829 31.95 40.877 ;
     RECT  33.012 40.829 33.066 40.877 ;
     RECT  34.092 40.829 34.905 40.877 ;
     RECT  7.815 40.865 8.874 40.901 ;
     RECT  7.815 40.901 8.838 40.937 ;
     RECT  10.8 40.835 10.818 40.973 ;
     RECT  26.892 40.739 26.91 40.973 ;
     RECT  28.548 40.865 28.566 40.973 ;
     RECT  30.852 40.877 30.87 40.973 ;
     RECT  33.048 40.877 33.066 40.973 ;
     RECT  34.596 40.877 34.905 40.973 ;
     RECT  25.344 40.865 25.434 40.979 ;
     RECT  7.815 40.937 8.37 41.009 ;
     RECT  20.484 40.865 20.502 41.009 ;
     RECT  23.508 40.865 24.105 41.009 ;
     RECT  25.344 40.979 25.362 41.009 ;
     RECT  38.988 40.865 39.006 41.009 ;
     RECT  2.415 40.787 2.505 41.057 ;
     RECT  7.815 41.009 7.905 41.057 ;
     RECT  13.215 40.865 13.305 41.057 ;
     RECT  18.615 40.865 18.705 41.057 ;
     RECT  24.015 41.009 24.105 41.057 ;
     RECT  29.415 40.829 29.505 41.057 ;
     RECT  34.815 40.973 34.905 41.057 ;
     RECT  40.215 40.787 40.305 41.057 ;
    LAYER M4 ;
     RECT  0.06 6.672 2.408 35.448 ;
     RECT  2.365 37.632 2.408 37.656 ;
     RECT  2.408 2.148 2.512 41.052 ;
     RECT  2.512 2.418 2.704 40.782 ;
     RECT  2.704 7.104 2.765 8.472 ;
     RECT  2.704 34.176 2.801 35.64 ;
     RECT  2.704 9.936 2.837 13.8 ;
     RECT  2.704 20.448 2.909 22.248 ;
     RECT  2.837 10.944 3.089 13.8 ;
     RECT  2.704 38.64 3.107 39.24 ;
     RECT  2.704 31.872 3.233 32.376 ;
     RECT  2.704 40.272 3.305 40.296 ;
     RECT  3.089 13.776 3.395 13.8 ;
     RECT  2.704 37.632 3.413 37.656 ;
     RECT  2.704 23.856 3.449 28.2 ;
     RECT  3.089 10.944 3.521 12.552 ;
     RECT  2.704 29.568 3.521 29.784 ;
     RECT  2.909 21.648 3.557 22.248 ;
     RECT  3.521 12 3.629 12.552 ;
     RECT  2.837 9.936 3.697 9.96 ;
     RECT  3.449 25.2 3.697 28.2 ;
     RECT  3.107 39.216 3.769 39.24 ;
     RECT  3.697 9.504 3.829 9.96 ;
     RECT  3.521 10.944 3.829 11.016 ;
     RECT  3.829 9.504 3.875 11.016 ;
     RECT  3.233 31.872 3.913 32.088 ;
     RECT  3.913 31.344 4.019 32.088 ;
     RECT  2.704 15.024 4.057 17.112 ;
     RECT  3.875 9.504 4.061 10.92 ;
     RECT  2.801 34.176 4.129 34.392 ;
     RECT  3.769 39.216 4.129 39.336 ;
     RECT  4.057 14.784 4.169 17.112 ;
     RECT  3.697 25.2 4.169 28.536 ;
     RECT  4.129 34.032 4.169 34.392 ;
     RECT  4.169 25.44 4.205 28.536 ;
     RECT  2.765 7.344 4.273 8.472 ;
     RECT  4.273 6.384 4.489 8.472 ;
     RECT  4.061 9.504 4.489 9.816 ;
     RECT  3.557 21.648 4.493 21.672 ;
     RECT  4.129 38.784 4.525 39.336 ;
     RECT  3.449 23.856 4.529 23.88 ;
     RECT  2.704 5.04 4.597 5.064 ;
     RECT  3.629 12.432 4.597 12.552 ;
     RECT  4.525 38.784 4.597 39.528 ;
     RECT  4.237 40.56 4.597 40.584 ;
     RECT  4.597 12.432 4.601 13.272 ;
     RECT  4.549 21.936 4.636 21.96 ;
     RECT  4.601 13.248 4.669 13.272 ;
     RECT  4.205 28.512 4.709 28.536 ;
     RECT  4.597 38.784 4.741 40.584 ;
     RECT  2.909 20.448 4.777 20.472 ;
     RECT  4.169 15.36 4.817 17.112 ;
     RECT  2.704 18.768 4.817 18.792 ;
     RECT  4.489 6.384 4.824 9.816 ;
     RECT  4.777 19.968 4.837 20.472 ;
     RECT  4.597 4.848 4.993 5.064 ;
     RECT  4.837 19.776 4.993 20.472 ;
     RECT  4.824 6.24 5.069 9.816 ;
     RECT  4.993 4.368 5.077 5.064 ;
     RECT  5.069 6.24 5.077 6.408 ;
     RECT  4.993 18.96 5.173 20.472 ;
     RECT  5.069 7.968 5.209 9.816 ;
     RECT  4.061 10.896 5.209 10.92 ;
     RECT  3.697 30.24 5.228 30.264 ;
     RECT  4.019 31.344 5.228 31.992 ;
     RECT  5.077 4.368 5.276 6.408 ;
     RECT  4.669 13.248 5.281 14.232 ;
     RECT  4.817 15.36 5.281 16.008 ;
     RECT  5.228 30.24 5.315 31.992 ;
     RECT  5.315 30.24 5.353 30.264 ;
     RECT  5.276 3.792 5.363 6.408 ;
     RECT  4.205 25.44 5.389 27.336 ;
     RECT  5.281 13.248 5.411 16.008 ;
     RECT  4.741 38.208 5.459 40.584 ;
     RECT  2.801 35.616 5.461 35.64 ;
     RECT  5.413 36.672 5.461 36.696 ;
     RECT  5.317 2.256 5.501 2.28 ;
     RECT  5.461 35.616 5.501 36.696 ;
     RECT  4.777 22.752 5.641 22.776 ;
     RECT  5.501 35.616 5.651 36.456 ;
     RECT  5.411 13.248 5.653 14.904 ;
     RECT  5.315 31.344 5.677 31.992 ;
     RECT  5.459 38.736 5.681 40.584 ;
     RECT  5.173 18.96 5.699 20.952 ;
     RECT  5.209 7.968 5.74 10.92 ;
     RECT  5.653 13.056 5.749 14.904 ;
     RECT  5.677 31.344 5.821 32.904 ;
     RECT  4.169 34.032 5.821 34.056 ;
     RECT  5.641 22.752 5.893 23.592 ;
     RECT  5.389 25.44 5.893 27.96 ;
     RECT  5.651 36.432 5.897 36.456 ;
     RECT  5.699 20.928 5.9 20.952 ;
     RECT  5.74 8.304 5.965 10.92 ;
     RECT  5.699 18.96 5.965 19.8 ;
     RECT  5.9 20.928 5.987 21.672 ;
     RECT  5.411 15.984 6.005 16.008 ;
     RECT  5.987 20.928 6.005 20.952 ;
     RECT  5.893 22.752 6.037 27.96 ;
     RECT  5.965 8.304 6.077 11.448 ;
     RECT  5.363 4.848 6.217 6.408 ;
     RECT  6.077 9.072 6.275 11.448 ;
     RECT  6.037 22.752 6.275 28.824 ;
     RECT  6.217 4.848 6.325 6.984 ;
     RECT  5.681 38.736 6.329 39.864 ;
     RECT  5.353 30.096 6.577 30.264 ;
     RECT  5.821 31.344 6.577 34.056 ;
     RECT  6.325 4.464 6.581 7.128 ;
     RECT  6.581 4.512 6.689 7.128 ;
     RECT  6.275 24.864 6.757 28.824 ;
     RECT  6.577 30.096 6.757 34.056 ;
     RECT  6.329 38.736 6.797 39.768 ;
     RECT  6.757 24.864 6.853 34.056 ;
     RECT  6.361 35.136 6.853 35.16 ;
     RECT  6.685 36.96 6.865 37.032 ;
     RECT  6.865 36.96 7.117 37.128 ;
     RECT  6.275 9.072 7.153 10.92 ;
     RECT  6.275 22.752 7.189 23.64 ;
     RECT  6.785 7.92 7.261 7.944 ;
     RECT  7.153 8.976 7.261 10.92 ;
     RECT  5.965 18 7.333 19.8 ;
     RECT  7.117 36.624 7.405 37.128 ;
     RECT  7.189 22.56 7.593 23.64 ;
     RECT  6.853 24.864 7.593 35.16 ;
     RECT  7.593 22.56 7.621 35.16 ;
     RECT  5.749 12.528 7.669 14.904 ;
     RECT  7.621 21.696 7.669 35.16 ;
     RECT  7.405 36.576 7.669 37.128 ;
     RECT  7.333 3.408 7.693 3.432 ;
     RECT  7.693 2.256 7.808 3.432 ;
     RECT  6.689 4.512 7.808 6.888 ;
     RECT  7.261 7.92 7.808 10.92 ;
     RECT  7.669 12.528 7.808 15.048 ;
     RECT  6.217 16.08 7.808 16.104 ;
     RECT  7.333 18 7.808 20.424 ;
     RECT  7.669 21.696 7.808 37.128 ;
     RECT  6.797 38.784 7.808 39.768 ;
     RECT  7.808 2.148 7.912 41.052 ;
     RECT  7.912 2.256 8.104 40.782 ;
     RECT  8.104 2.256 8.243 3.048 ;
     RECT  8.104 36.048 8.345 37.608 ;
     RECT  8.104 17.616 8.489 34.488 ;
     RECT  8.243 2.592 8.561 3.048 ;
     RECT  8.104 38.784 8.561 40.44 ;
     RECT  8.104 4.512 8.633 4.728 ;
     RECT  8.489 17.616 8.705 34.104 ;
     RECT  8.104 13.056 8.849 16.104 ;
     RECT  8.705 17.616 8.885 33.096 ;
     RECT  8.345 36.048 8.921 36.264 ;
     RECT  8.104 8.448 8.957 10.392 ;
     RECT  8.561 38.784 8.957 38.808 ;
     RECT  8.849 15.024 9.029 16.104 ;
     RECT  8.561 40.416 9.029 40.44 ;
     RECT  8.957 8.448 9.173 10.2 ;
     RECT  8.885 33.024 9.173 33.096 ;
     RECT  8.104 11.952 9.205 11.976 ;
     RECT  8.849 13.056 9.205 13.608 ;
     RECT  8.921 36.048 9.241 36.072 ;
     RECT  8.885 17.616 9.317 31.752 ;
     RECT  9.205 5.424 9.385 5.448 ;
     RECT  8.104 6.576 9.385 6.936 ;
     RECT  9.029 15.744 9.457 16.104 ;
     RECT  9.205 11.952 9.569 13.608 ;
     RECT  9.173 8.448 9.692 9.864 ;
     RECT  9.385 5.424 9.733 6.936 ;
     RECT  8.705 34.08 9.749 34.104 ;
     RECT  8.561 2.592 9.853 2.616 ;
     RECT  9.173 33.072 10.033 33.096 ;
     RECT  9.457 15.744 10.069 16.872 ;
     RECT  9.241 35.904 10.069 36.072 ;
     RECT  8.345 37.536 10.069 37.608 ;
     RECT  10.105 40.272 10.141 40.296 ;
     RECT  10.141 38.592 10.22 38.616 ;
     RECT  10.141 40.272 10.22 40.824 ;
     RECT  9.692 8.16 10.261 9.864 ;
     RECT  10.261 8.16 10.307 10.296 ;
     RECT  10.22 38.592 10.307 40.824 ;
     RECT  9.853 2.256 10.325 2.616 ;
     RECT  9.317 18.144 10.325 31.752 ;
     RECT  10.307 40.272 10.397 40.824 ;
     RECT  10.325 18.192 10.453 31.752 ;
     RECT  10.033 33.072 10.453 33.432 ;
     RECT  9.733 5.424 10.469 7.176 ;
     RECT  10.453 18.192 10.505 33.432 ;
     RECT  10.469 5.424 10.537 6.888 ;
     RECT  9.569 11.952 10.604 13.56 ;
     RECT  9.529 3.984 10.609 4.008 ;
     RECT  10.537 5.136 10.609 6.888 ;
     RECT  10.505 18.192 10.649 20.52 ;
     RECT  10.505 21.504 10.649 22.2 ;
     RECT  10.649 18.432 10.685 20.52 ;
     RECT  10.604 11.952 10.691 14.232 ;
     RECT  10.069 15.216 10.825 16.872 ;
     RECT  10.069 35.904 10.825 37.608 ;
     RECT  10.691 11.952 10.829 13.56 ;
     RECT  10.397 40.8 10.829 40.824 ;
     RECT  10.307 9.072 10.865 10.296 ;
     RECT  10.829 11.952 10.865 13.464 ;
     RECT  10.325 2.256 10.883 2.52 ;
     RECT  10.609 3.984 10.883 6.888 ;
     RECT  10.825 15.216 10.897 16.92 ;
     RECT  10.573 7.92 10.901 8.04 ;
     RECT  10.883 2.496 10.909 2.52 ;
     RECT  10.825 35.52 10.933 37.608 ;
     RECT  10.685 19.584 10.937 20.52 ;
     RECT  10.897 14.784 11.009 16.92 ;
     RECT  10.505 23.328 11.027 33.432 ;
     RECT  10.901 7.968 11.045 8.04 ;
     RECT  10.865 11.952 11.117 13.416 ;
     RECT  10.933 34.608 11.117 37.608 ;
     RECT  10.865 9.36 11.185 10.296 ;
     RECT  11.149 11.328 11.185 11.352 ;
     RECT  11.185 9.36 11.189 11.352 ;
     RECT  10.883 5.04 11.297 6.888 ;
     RECT  10.649 22.176 11.333 22.2 ;
     RECT  11.117 34.608 11.459 35.976 ;
     RECT  11.009 14.832 11.513 16.92 ;
     RECT  11.117 37.296 11.513 37.608 ;
     RECT  10.685 18.432 11.905 18.552 ;
     RECT  10.937 19.584 11.905 19.8 ;
     RECT  11.513 15.984 11.948 16.92 ;
     RECT  11.905 18.432 11.948 19.8 ;
     RECT  11.513 14.832 11.977 14.856 ;
     RECT  11.977 14.4 12.017 14.856 ;
     RECT  12.013 2.496 12.049 2.52 ;
     RECT  11.297 5.328 12.121 6.888 ;
     RECT  11.045 7.968 12.121 7.992 ;
     RECT  11.189 9.6 12.121 11.352 ;
     RECT  11.117 12.336 12.121 13.416 ;
     RECT  11.948 15.984 12.193 19.8 ;
     RECT  12.193 15.984 12.229 19.944 ;
     RECT  11.941 22.56 12.445 22.584 ;
     RECT  11.027 23.616 12.445 33.432 ;
     RECT  11.459 34.752 12.481 35.976 ;
     RECT  11.513 37.584 12.481 37.608 ;
     RECT  12.445 22.56 12.524 33.432 ;
     RECT  12.229 15.984 12.553 21.144 ;
     RECT  12.524 22.176 12.553 33.432 ;
     RECT  12.481 34.752 12.553 37.608 ;
     RECT  12.517 4.176 12.589 4.2 ;
     RECT  12.121 5.328 12.589 6.936 ;
     RECT  12.553 15.984 12.589 33.432 ;
     RECT  12.553 34.752 12.589 37.704 ;
     RECT  12.049 2.496 12.613 2.856 ;
     RECT  12.589 4.176 12.613 6.936 ;
     RECT  12.121 7.968 12.613 8.472 ;
     RECT  12.589 15.984 12.697 37.704 ;
     RECT  12.613 2.496 13.057 8.472 ;
     RECT  13.057 2.496 13.093 8.52 ;
     RECT  12.121 9.6 13.093 13.416 ;
     RECT  13.093 2.496 13.208 13.416 ;
     RECT  12.017 14.4 13.208 14.424 ;
     RECT  12.697 15.984 13.208 38.712 ;
     RECT  11.761 40.464 13.208 40.488 ;
     RECT  13.208 2.148 13.312 41.052 ;
     RECT  13.312 2.418 13.504 40.782 ;
     RECT  13.504 24.912 13.565 34.392 ;
     RECT  13.504 3.36 13.781 19.608 ;
     RECT  13.781 3.36 13.853 13.704 ;
     RECT  13.504 35.424 14.14 39.96 ;
     RECT  13.565 24.912 14.141 33.048 ;
     RECT  14.141 24.912 14.285 33 ;
     RECT  13.565 34.032 14.339 34.392 ;
     RECT  14.339 34.032 14.357 34.2 ;
     RECT  14.14 35.424 14.38 37.656 ;
     RECT  14.38 35.52 14.393 37.656 ;
     RECT  14.14 38.688 14.393 39.96 ;
     RECT  14.393 35.52 14.609 36.648 ;
     RECT  13.781 14.784 14.713 19.608 ;
     RECT  13.504 20.592 14.713 23.928 ;
     RECT  14.713 14.784 14.861 23.928 ;
     RECT  14.393 39.312 14.861 39.96 ;
     RECT  14.861 18.288 14.929 23.928 ;
     RECT  14.285 24.912 14.929 27.72 ;
     RECT  14.929 18.288 14.969 27.72 ;
     RECT  14.861 14.784 15.037 16.872 ;
     RECT  13.853 3.36 15.145 8.52 ;
     RECT  13.853 9.6 15.145 13.704 ;
     RECT  15.145 3.36 15.253 13.704 ;
     RECT  14.969 22.272 15.289 27.72 ;
     RECT  15.212 2.256 15.299 2.28 ;
     RECT  15.253 3.312 15.349 13.704 ;
     RECT  15.037 14.736 15.349 16.872 ;
     RECT  15.349 3.312 15.365 16.872 ;
     RECT  14.609 35.52 15.401 35.928 ;
     RECT  15.289 22.272 15.505 27.768 ;
     RECT  14.285 28.8 15.505 33 ;
     RECT  15.505 22.272 15.541 33 ;
     RECT  14.357 34.176 15.541 34.2 ;
     RECT  14.969 18.288 15.869 21.048 ;
     RECT  14.393 37.632 15.973 37.656 ;
     RECT  14.861 39.312 15.973 39.336 ;
     RECT  15.541 22.272 16.012 34.2 ;
     RECT  15.365 11.424 16.013 16.872 ;
     RECT  15.869 18.288 16.032 21 ;
     RECT  16.032 18.288 16.049 20.952 ;
     RECT  15.973 37.44 16.049 39.336 ;
     RECT  16.049 37.44 16.157 38.568 ;
     RECT  16.157 37.44 16.189 38.184 ;
     RECT  15.401 35.52 16.333 35.592 ;
     RECT  16.013 11.424 16.337 13.464 ;
     RECT  15.365 3.312 16.409 9.624 ;
     RECT  16.189 36.912 16.409 38.184 ;
     RECT  16.409 3.312 16.445 7.416 ;
     RECT  16.337 11.424 16.513 11.448 ;
     RECT  16.445 3.312 16.549 5.736 ;
     RECT  16.333 35.328 16.585 35.592 ;
     RECT  16.585 35.328 16.625 35.736 ;
     RECT  16.409 8.496 16.729 9.624 ;
     RECT  16.013 14.736 16.789 16.872 ;
     RECT  16.049 18.288 16.789 20.616 ;
     RECT  16.012 22.416 16.877 34.2 ;
     RECT  16.877 22.752 17.021 34.2 ;
     RECT  16.789 14.736 17.053 20.616 ;
     RECT  17.053 14.736 17.089 20.904 ;
     RECT  16.549 2.88 17.123 5.736 ;
     RECT  17.123 2.88 17.129 4.2 ;
     RECT  16.337 12.48 17.197 13.464 ;
     RECT  17.089 14.736 17.197 21.192 ;
     RECT  17.123 5.424 17.273 5.736 ;
     RECT  16.445 6.768 17.363 7.416 ;
     RECT  17.273 5.424 17.561 5.448 ;
     RECT  16.409 36.912 17.597 36.936 ;
     RECT  17.161 40.704 17.881 40.728 ;
     RECT  16.729 8.496 17.948 10.248 ;
     RECT  16.513 11.232 17.948 11.448 ;
     RECT  17.881 39.792 17.989 40.728 ;
     RECT  16.409 38.16 18.161 38.184 ;
     RECT  17.989 39.504 18.161 40.728 ;
     RECT  17.021 34.176 18.205 34.2 ;
     RECT  16.625 35.52 18.205 35.736 ;
     RECT  17.363 6.768 18.385 7.272 ;
     RECT  17.129 3.408 18.469 4.2 ;
     RECT  18.161 38.16 18.469 40.728 ;
     RECT  17.197 12.48 18.529 21.192 ;
     RECT  17.021 22.752 18.529 33.096 ;
     RECT  18.469 3.408 18.608 4.68 ;
     RECT  18.385 6.288 18.608 7.272 ;
     RECT  17.948 8.496 18.608 11.448 ;
     RECT  18.529 12.48 18.608 33.096 ;
     RECT  18.205 34.176 18.608 35.736 ;
     RECT  18.469 37.584 18.608 40.728 ;
     RECT  18.608 2.148 18.712 41.052 ;
     RECT  18.712 2.304 18.904 40.782 ;
     RECT  18.904 12.48 19.109 33.048 ;
     RECT  19.109 12.48 19.187 32.856 ;
     RECT  18.904 34.368 19.187 38.76 ;
     RECT  18.904 2.304 19.217 4.2 ;
     RECT  18.904 6.288 19.253 11.352 ;
     RECT  19.187 12.48 19.433 16.536 ;
     RECT  19.217 2.304 19.541 3.864 ;
     RECT  18.904 39.792 19.613 40.584 ;
     RECT  19.613 39.888 19.708 40.584 ;
     RECT  19.187 34.368 19.756 38.52 ;
     RECT  19.756 37.392 19.901 38.52 ;
     RECT  19.756 34.368 20.149 35.928 ;
     RECT  19.433 12.48 20.257 14.472 ;
     RECT  19.187 17.712 20.369 32.856 ;
     RECT  19.253 6.384 20.441 11.352 ;
     RECT  19.901 37.392 20.441 38.376 ;
     RECT  19.708 39.888 20.441 40.44 ;
     RECT  20.293 5.136 20.477 5.16 ;
     RECT  20.149 33.936 20.483 35.928 ;
     RECT  20.257 12.384 20.549 14.472 ;
     RECT  20.492 0.096 20.579 0.12 ;
     RECT  19.433 15.504 20.585 16.536 ;
     RECT  19.541 2.304 20.617 3.816 ;
     RECT  20.549 14.448 20.617 14.472 ;
     RECT  20.585 15.504 20.617 16.44 ;
     RECT  20.617 14.448 20.657 16.44 ;
     RECT  20.441 37.584 20.657 38.376 ;
     RECT  20.441 6.384 20.761 11.304 ;
     RECT  20.617 2.304 20.801 3.96 ;
     RECT  20.801 2.304 20.909 2.328 ;
     RECT  20.483 34.032 20.981 35.928 ;
     RECT  20.549 12.384 21.089 13.464 ;
     RECT  20.761 5.808 21.125 11.304 ;
     RECT  20.657 37.68 21.125 38.376 ;
     RECT  20.441 39.888 21.301 40.008 ;
     RECT  20.369 32.832 21.341 32.856 ;
     RECT  20.981 34.032 21.377 35.88 ;
     RECT  20.369 17.712 21.481 31.752 ;
     RECT  21.481 17.712 21.541 31.944 ;
     RECT  20.657 14.784 21.553 16.44 ;
     RECT  21.125 5.808 21.589 5.832 ;
     RECT  21.089 12.48 21.589 13.464 ;
     RECT  21.553 14.784 21.676 16.584 ;
     RECT  21.125 6.816 21.683 11.304 ;
     RECT  21.125 37.68 21.697 37.704 ;
     RECT  21.676 15.504 21.841 16.584 ;
     RECT  21.541 17.616 21.841 31.944 ;
     RECT  21.841 15.504 21.881 31.944 ;
     RECT  21.377 34.176 22.057 35.88 ;
     RECT  21.697 37.008 22.057 37.704 ;
     RECT  21.589 12.48 22.093 13.608 ;
     RECT  21.301 39.312 22.165 40.008 ;
     RECT  21.881 15.936 22.169 31.944 ;
     RECT  21.683 6.864 22.277 11.304 ;
     RECT  22.165 38.832 22.381 40.008 ;
     RECT  22.057 34.176 22.597 37.704 ;
     RECT  21.589 5.712 22.601 5.832 ;
     RECT  22.169 15.936 22.601 25.272 ;
     RECT  22.597 33.936 22.633 37.704 ;
     RECT  22.633 33.936 22.705 37.752 ;
     RECT  22.381 38.784 22.705 40.008 ;
     RECT  22.169 26.832 22.741 31.944 ;
     RECT  22.705 33.936 22.741 40.008 ;
     RECT  22.309 2.256 22.789 2.28 ;
     RECT  20.801 3.408 22.789 3.96 ;
     RECT  22.741 33.408 22.825 40.008 ;
     RECT  22.789 2.256 22.835 3.96 ;
     RECT  22.835 2.496 22.849 3.96 ;
     RECT  22.741 26.832 22.957 32.232 ;
     RECT  22.277 7.008 23.029 11.304 ;
     RECT  22.093 12.48 23.029 14.472 ;
     RECT  22.825 37.056 23.065 40.008 ;
     RECT  22.849 2.496 23.245 4.44 ;
     RECT  22.601 5.712 23.245 5.736 ;
     RECT  22.601 18.48 23.317 25.272 ;
     RECT  23.317 18.48 23.533 25.608 ;
     RECT  22.957 26.832 23.533 32.28 ;
     RECT  23.533 18.48 23.569 32.28 ;
     RECT  22.825 33.408 23.569 36.024 ;
     RECT  22.601 15.936 23.785 17.448 ;
     RECT  23.065 37.056 23.857 40.632 ;
     RECT  23.785 15.456 23.893 17.448 ;
     RECT  23.569 18.48 23.893 36.024 ;
     RECT  23.245 2.496 24.008 5.736 ;
     RECT  23.029 7.008 24.008 14.472 ;
     RECT  23.893 15.456 24.008 36.024 ;
     RECT  23.857 37.056 24.008 40.968 ;
     RECT  24.008 2.148 24.112 41.052 ;
     RECT  24.112 2.256 24.304 40.968 ;
     RECT  24.304 37.68 24.437 37.704 ;
     RECT  24.304 17.328 24.563 32.28 ;
     RECT  24.304 2.256 24.581 3.288 ;
     RECT  24.304 4.752 24.707 16.104 ;
     RECT  24.707 4.752 24.833 13.464 ;
     RECT  24.833 4.752 24.905 10.68 ;
     RECT  24.905 6.288 24.941 10.68 ;
     RECT  24.833 12 25.013 13.464 ;
     RECT  24.563 19.584 25.021 32.28 ;
     RECT  24.941 7.392 25.085 10.68 ;
     RECT  24.304 34.032 25.157 36.024 ;
     RECT  24.304 39.504 25.157 39.528 ;
     RECT  25.021 23.616 25.229 32.28 ;
     RECT  24.304 40.608 25.445 40.968 ;
     RECT  24.707 14.88 25.484 16.104 ;
     RECT  25.297 38.448 25.513 38.472 ;
     RECT  25.484 14.88 25.571 16.248 ;
     RECT  24.581 2.256 25.805 2.28 ;
     RECT  25.229 23.616 25.877 27.72 ;
     RECT  24.581 3.264 25.949 3.288 ;
     RECT  24.941 6.288 26.017 6.312 ;
     RECT  25.085 7.392 26.017 10.2 ;
     RECT  25.445 40.608 26.017 40.632 ;
     RECT  24.905 4.752 26.101 5.208 ;
     RECT  26.017 6.288 26.101 10.2 ;
     RECT  26.101 4.752 26.125 10.2 ;
     RECT  25.157 34.032 26.125 35.592 ;
     RECT  25.013 12.48 26.161 13.464 ;
     RECT  26.125 4.176 26.189 10.2 ;
     RECT  26.125 34.032 26.237 36.264 ;
     RECT  26.189 4.176 26.273 10.872 ;
     RECT  26.237 34.08 26.309 36.264 ;
     RECT  25.877 26.256 26.377 27.72 ;
     RECT  25.229 28.752 26.377 32.28 ;
     RECT  25.513 38.448 26.377 38.52 ;
     RECT  26.017 39.744 26.377 40.632 ;
     RECT  26.377 26.256 26.525 32.28 ;
     RECT  24.563 17.328 26.557 18.504 ;
     RECT  25.021 19.584 26.557 22.632 ;
     RECT  26.377 38.448 26.557 40.632 ;
     RECT  25.571 14.88 26.561 16.104 ;
     RECT  26.561 15.504 26.701 16.104 ;
     RECT  26.557 17.328 26.701 22.632 ;
     RECT  26.701 15.504 26.777 22.632 ;
     RECT  26.557 37.872 26.813 40.632 ;
     RECT  26.273 4.176 26.849 10.2 ;
     RECT  26.777 15.552 26.849 22.632 ;
     RECT  25.877 23.616 26.849 25.272 ;
     RECT  26.849 4.176 27.137 10.056 ;
     RECT  26.377 2.832 27.253 2.856 ;
     RECT  27.169 3.888 27.253 3.912 ;
     RECT  26.849 23.856 27.349 25.272 ;
     RECT  26.525 26.256 27.349 32.232 ;
     RECT  26.849 15.552 27.461 22.584 ;
     RECT  26.813 39.504 27.529 40.632 ;
     RECT  27.349 23.856 27.565 32.232 ;
     RECT  26.161 11.952 27.673 13.464 ;
     RECT  26.813 37.872 27.889 37.896 ;
     RECT  26.309 34.32 27.925 36.264 ;
     RECT  27.461 17.328 27.929 22.584 ;
     RECT  27.565 23.856 27.971 32.472 ;
     RECT  27.529 39.504 28.021 40.728 ;
     RECT  27.137 5.184 28.073 10.056 ;
     RECT  27.925 33.648 28.249 36.264 ;
     RECT  28.073 5.184 28.259 6.696 ;
     RECT  27.889 37.632 28.285 37.896 ;
     RECT  27.253 2.688 28.309 3.912 ;
     RECT  28.073 7.68 28.357 10.056 ;
     RECT  28.309 2.256 28.361 3.912 ;
     RECT  28.361 2.256 28.396 2.808 ;
     RECT  28.357 7.68 28.397 10.248 ;
     RECT  28.249 33.456 28.429 36.264 ;
     RECT  28.285 37.392 28.429 37.896 ;
     RECT  27.461 15.552 28.453 16.104 ;
     RECT  28.397 10.176 28.501 10.248 ;
     RECT  27.673 11.28 28.501 13.464 ;
     RECT  28.429 33.456 28.501 37.896 ;
     RECT  28.021 39.024 28.501 40.728 ;
     RECT  27.971 23.856 28.537 32.28 ;
     RECT  27.929 18.432 28.609 22.584 ;
     RECT  28.537 23.712 28.609 32.28 ;
     RECT  28.501 10.176 28.753 13.464 ;
     RECT  28.453 15.024 28.753 16.104 ;
     RECT  27.929 17.328 28.861 17.448 ;
     RECT  28.645 3.984 29.041 4.008 ;
     RECT  28.861 17.088 29.041 17.448 ;
     RECT  28.609 18.432 29.041 32.28 ;
     RECT  28.397 7.68 29.365 9.144 ;
     RECT  28.753 10.176 29.365 16.104 ;
     RECT  28.396 2.736 29.408 2.808 ;
     RECT  29.041 3.984 29.408 4.488 ;
     RECT  28.259 5.808 29.408 6.696 ;
     RECT  29.365 7.68 29.408 16.104 ;
     RECT  29.041 17.088 29.408 32.28 ;
     RECT  28.501 33.456 29.408 40.728 ;
     RECT  29.408 2.148 29.512 41.052 ;
     RECT  29.512 2.418 29.704 40.782 ;
     RECT  29.704 34.368 29.801 40.782 ;
     RECT  29.704 25.728 29.843 30.696 ;
     RECT  29.801 39.504 29.843 40.782 ;
     RECT  29.704 2.784 30.125 3.096 ;
     RECT  29.801 34.368 30.125 38.424 ;
     RECT  30.125 34.656 30.227 38.424 ;
     RECT  29.704 4.464 30.275 23.976 ;
     RECT  30.275 9.744 30.305 23.976 ;
     RECT  30.305 9.744 30.341 17.208 ;
     RECT  30.305 18.288 30.629 23.976 ;
     RECT  29.843 39.6 30.629 40.782 ;
     RECT  30.629 40.368 30.661 40.782 ;
     RECT  30.125 2.832 30.769 3.096 ;
     RECT  30.275 4.464 30.769 8.712 ;
     RECT  30.769 2.832 30.809 8.712 ;
     RECT  30.809 2.832 30.853 8.568 ;
     RECT  30.629 19.488 30.881 23.976 ;
     RECT  29.704 31.728 30.901 32.808 ;
     RECT  30.853 2.832 30.917 3.096 ;
     RECT  30.341 9.744 30.917 16.968 ;
     RECT  30.881 19.584 30.985 23.976 ;
     RECT  30.985 19.584 31.057 24.168 ;
     RECT  29.843 25.728 31.057 30.504 ;
     RECT  30.917 9.744 31.097 13.848 ;
     RECT  30.629 18.288 31.273 18.504 ;
     RECT  31.057 19.584 31.309 30.504 ;
     RECT  30.901 31.728 31.309 33.528 ;
     RECT  31.309 19.584 31.34 33.528 ;
     RECT  30.227 34.656 31.34 38.136 ;
     RECT  30.917 2.832 31.385 2.904 ;
     RECT  31.34 19.584 31.427 38.136 ;
     RECT  31.427 34.656 31.489 38.136 ;
     RECT  30.917 15.216 31.525 16.968 ;
     RECT  31.273 17.952 31.525 18.504 ;
     RECT  31.385 2.832 31.601 2.856 ;
     RECT  31.489 34.656 31.621 39.336 ;
     RECT  30.661 40.368 31.621 40.872 ;
     RECT  30.853 4.272 31.907 8.568 ;
     RECT  31.907 6.336 31.961 8.568 ;
     RECT  31.621 34.656 31.997 40.872 ;
     RECT  31.525 15.216 32.065 18.504 ;
     RECT  31.427 19.584 32.065 33.144 ;
     RECT  32.065 15.216 32.177 33.144 ;
     RECT  31.961 8.304 32.281 8.568 ;
     RECT  31.097 9.744 32.281 11.256 ;
     RECT  32.177 15.216 32.321 22.584 ;
     RECT  32.177 23.568 32.425 33.144 ;
     RECT  31.097 12.384 32.461 13.848 ;
     RECT  32.281 8.304 32.465 11.256 ;
     RECT  31.997 34.656 32.483 39.048 ;
     RECT  32.461 12.384 32.569 13.944 ;
     RECT  32.569 12.288 32.713 13.944 ;
     RECT  32.713 12.288 32.749 13.992 ;
     RECT  31.907 4.512 32.917 5.256 ;
     RECT  32.465 11.136 32.917 11.256 ;
     RECT  32.749 12.288 32.917 14.136 ;
     RECT  31.961 6.336 32.963 6.84 ;
     RECT  32.483 34.704 33.001 39.048 ;
     RECT  31.997 40.368 33.001 40.872 ;
     RECT  32.465 8.304 33.004 10.104 ;
     RECT  33.004 8.304 33.059 9.144 ;
     RECT  33.059 8.304 33.181 8.568 ;
     RECT  32.963 6.384 33.253 6.84 ;
     RECT  33.181 7.968 33.253 8.568 ;
     RECT  32.497 2.88 33.289 2.904 ;
     RECT  33.001 34.704 33.293 40.872 ;
     RECT  33.289 2.304 33.329 2.904 ;
     RECT  32.321 16.944 33.329 22.584 ;
     RECT  32.425 23.568 33.365 33.528 ;
     RECT  32.321 15.216 33.433 15.864 ;
     RECT  33.329 16.944 33.433 21.48 ;
     RECT  33.329 22.464 33.469 22.584 ;
     RECT  33.365 23.568 33.469 28.296 ;
     RECT  32.917 11.136 33.541 14.136 ;
     RECT  33.433 15.216 33.541 21.48 ;
     RECT  33.293 34.704 33.587 38.088 ;
     RECT  33.365 29.28 33.649 33.528 ;
     RECT  33.587 34.704 33.649 37.992 ;
     RECT  33.541 11.136 33.901 21.48 ;
     RECT  33.253 6.384 34.153 8.568 ;
     RECT  34.153 6.384 34.261 8.616 ;
     RECT  34.261 6.384 34.477 9 ;
     RECT  33.469 22.464 34.477 28.296 ;
     RECT  33.649 29.28 34.477 37.992 ;
     RECT  32.917 4.512 34.693 5.304 ;
     RECT  34.477 6.336 34.693 9 ;
     RECT  33.329 2.304 34.808 2.328 ;
     RECT  34.693 4.512 34.808 9 ;
     RECT  33.901 10.32 34.808 21.48 ;
     RECT  34.477 22.464 34.808 37.992 ;
     RECT  33.293 39.264 34.808 40.872 ;
     RECT  34.808 2.148 34.912 41.052 ;
     RECT  34.912 2.304 35.104 40.782 ;
     RECT  35.104 17.472 35.165 17.496 ;
     RECT  35.104 18.48 35.165 22.584 ;
     RECT  35.104 2.304 35.237 15.432 ;
     RECT  35.237 10.608 35.267 15.432 ;
     RECT  35.104 23.616 35.309 35.928 ;
     RECT  35.309 32.592 35.381 35.928 ;
     RECT  35.309 23.616 35.453 30.792 ;
     RECT  35.237 2.304 35.603 9.528 ;
     RECT  35.603 2.304 35.749 2.904 ;
     RECT  35.267 14.16 35.821 15.432 ;
     RECT  35.603 3.888 35.843 9.528 ;
     RECT  35.749 2.304 35.957 2.808 ;
     RECT  35.843 3.888 35.957 7.608 ;
     RECT  35.453 23.616 35.957 23.976 ;
     RECT  35.453 25.056 36.083 30.792 ;
     RECT  35.957 2.304 36.097 2.328 ;
     RECT  36.097 2.256 36.181 2.328 ;
     RECT  36.133 16.56 36.205 16.584 ;
     RECT  35.957 3.888 36.209 3.912 ;
     RECT  35.267 10.608 36.275 12.936 ;
     RECT  36.205 16.56 36.277 16.728 ;
     RECT  35.165 18.672 36.277 22.584 ;
     RECT  35.957 23.616 36.277 23.928 ;
     RECT  35.381 33.648 36.277 35.928 ;
     RECT  35.104 37.056 36.277 38.184 ;
     RECT  36.277 33.648 36.421 38.184 ;
     RECT  35.104 39.264 36.421 39.288 ;
     RECT  36.083 28.464 36.457 30.792 ;
     RECT  36.083 25.056 36.533 26.904 ;
     RECT  36.277 18.672 36.569 23.928 ;
     RECT  36.457 28.464 36.713 31.56 ;
     RECT  35.821 14.16 36.817 14.808 ;
     RECT  36.275 10.608 36.821 12.552 ;
     RECT  36.569 19.344 36.851 23.928 ;
     RECT  35.381 32.592 36.889 32.616 ;
     RECT  36.421 33.648 36.889 39.288 ;
     RECT  36.851 20.784 37.001 23.928 ;
     RECT  36.181 2.304 37.033 2.328 ;
     RECT  37.033 2.304 37.073 2.856 ;
     RECT  35.843 9.504 37.073 9.528 ;
     RECT  36.889 32.592 37.105 39.288 ;
     RECT  35.957 5.04 37.141 5.448 ;
     RECT  35.957 6.528 37.141 7.608 ;
     RECT  36.277 16.512 37.285 16.728 ;
     RECT  37.105 32.544 37.285 39.288 ;
     RECT  37.285 31.92 37.325 39.288 ;
     RECT  36.713 28.464 37.465 30.696 ;
     RECT  37.325 31.92 37.475 36.36 ;
     RECT  36.817 14.16 37.573 14.904 ;
     RECT  37.285 16.512 37.573 17.352 ;
     RECT  36.851 19.344 37.609 19.368 ;
     RECT  37.573 14.16 37.621 17.352 ;
     RECT  37.609 18.768 37.621 19.368 ;
     RECT  37.475 31.92 37.649 32.616 ;
     RECT  35.104 40.272 37.649 40.488 ;
     RECT  37.621 14.16 37.667 19.368 ;
     RECT  37.475 34.128 37.667 36.36 ;
     RECT  37.073 2.832 37.825 2.856 ;
     RECT  37.033 3.936 37.825 3.96 ;
     RECT  37.667 14.16 37.865 16.728 ;
     RECT  37.667 17.808 37.897 19.368 ;
     RECT  37.001 20.784 37.897 23.4 ;
     RECT  37.325 37.392 37.897 39.288 ;
     RECT  37.649 40.272 37.897 40.392 ;
     RECT  37.667 35.136 37.901 36.36 ;
     RECT  37.865 14.16 37.937 15.048 ;
     RECT  37.897 17.808 38.003 23.4 ;
     RECT  38.003 20.496 38.005 23.4 ;
     RECT  37.465 28.416 38.005 30.696 ;
     RECT  37.649 31.92 38.005 32.376 ;
     RECT  38.003 17.808 38.017 19.368 ;
     RECT  36.533 25.68 38.041 26.904 ;
     RECT  38.005 28.416 38.041 32.376 ;
     RECT  38.041 25.68 38.051 32.376 ;
     RECT  37.667 34.128 38.081 34.152 ;
     RECT  38.051 25.68 38.092 30.984 ;
     RECT  37.825 2.832 38.149 3.96 ;
     RECT  37.897 37.392 38.153 40.392 ;
     RECT  38.017 17.808 38.261 18.024 ;
     RECT  38.149 2.256 38.401 3.96 ;
     RECT  37.141 5.04 38.401 8.568 ;
     RECT  37.865 16.512 38.441 16.728 ;
     RECT  38.401 2.256 38.477 8.568 ;
     RECT  38.092 25.68 38.477 30.744 ;
     RECT  38.477 3.312 38.492 8.568 ;
     RECT  37.937 14.208 38.549 15.048 ;
     RECT  38.492 3.312 38.579 8.712 ;
     RECT  38.579 5.616 38.617 8.712 ;
     RECT  38.365 9.792 38.617 9.816 ;
     RECT  38.477 25.68 38.621 30.024 ;
     RECT  38.617 5.616 38.689 9.816 ;
     RECT  36.821 11.088 38.689 12.552 ;
     RECT  38.153 37.392 38.689 38.424 ;
     RECT  38.689 5.616 38.729 12.552 ;
     RECT  38.005 20.496 38.761 23.736 ;
     RECT  38.729 5.616 38.765 9.24 ;
     RECT  38.579 3.312 38.801 4.152 ;
     RECT  38.765 5.616 38.837 9.144 ;
     RECT  38.441 16.704 38.837 16.728 ;
     RECT  38.761 20.496 38.837 24.264 ;
     RECT  38.837 22.8 38.867 24.264 ;
     RECT  38.621 25.68 38.873 29.064 ;
     RECT  38.873 25.68 38.881 25.704 ;
     RECT  38.873 27.024 38.908 29.064 ;
     RECT  38.729 11.424 38.917 12.552 ;
     RECT  38.908 27.552 38.945 29.064 ;
     RECT  38.917 11.424 38.963 13.368 ;
     RECT  37.901 35.136 38.981 35.544 ;
     RECT  38.981 35.136 39.013 35.352 ;
     RECT  38.837 5.616 39.053 8.472 ;
     RECT  38.729 10.224 39.053 10.248 ;
     RECT  38.945 27.552 39.053 28.44 ;
     RECT  39.053 5.616 39.059 8.184 ;
     RECT  39.013 34.752 39.059 35.352 ;
     RECT  38.549 14.88 39.089 15 ;
     RECT  39.059 34.752 39.1 34.776 ;
     RECT  38.017 19.344 39.109 19.368 ;
     RECT  39.089 14.88 39.125 14.952 ;
     RECT  39.109 19.344 39.155 20.232 ;
     RECT  39.053 28.416 39.197 28.44 ;
     RECT  38.837 21.216 39.216 21.24 ;
     RECT  38.689 37.344 39.301 38.424 ;
     RECT  38.153 39.792 39.301 40.392 ;
     RECT  39.301 37.344 39.925 40.392 ;
     RECT  38.477 2.256 40.208 2.28 ;
     RECT  38.801 3.312 40.208 3.336 ;
     RECT  39.059 5.616 40.208 6.552 ;
     RECT  39.059 7.584 40.208 7.608 ;
     RECT  38.963 11.424 40.208 11.448 ;
     RECT  38.963 13.248 40.208 13.368 ;
     RECT  39.125 14.928 40.208 14.952 ;
     RECT  38.261 18 40.208 18.024 ;
     RECT  39.155 20.208 40.208 20.232 ;
     RECT  38.867 22.8 40.208 23.352 ;
     RECT  38.051 32.352 40.208 32.376 ;
     RECT  39.013 33.408 40.208 33.432 ;
     RECT  39.925 37.008 40.208 40.392 ;
     RECT  40.208 2.148 40.312 41.052 ;
     RECT  40.312 2.418 40.504 40.782 ;
     RECT  41.605 23.328 41.857 23.352 ;
     RECT  41.569 9.168 42.145 10.056 ;
     RECT  41.569 11.664 42.145 11.688 ;
     RECT  40.504 12.912 42.145 12.936 ;
     RECT  41.569 14.16 42.145 14.184 ;
     RECT  41.569 16.656 42.145 19.608 ;
     RECT  41.857 23.328 42.145 24.216 ;
     RECT  41.533 27.504 42.145 27.528 ;
     RECT  41.569 31.248 42.145 31.272 ;
     RECT  41.605 34.608 42.145 34.632 ;
     RECT  42.145 6.672 42.181 11.688 ;
     RECT  42.145 12.912 42.181 35.448 ;
     RECT  42.181 6.672 43.164 35.448 ;
    LAYER M5 ;
     RECT  2.4 2.137 2.52 2.151 ;
     RECT  7.8 2.137 7.92 2.151 ;
     RECT  13.2 2.137 13.32 2.151 ;
     RECT  18.6 2.137 18.72 2.151 ;
     RECT  24 2.137 24.12 2.151 ;
     RECT  29.4 2.137 29.52 2.151 ;
     RECT  34.8 2.137 34.92 2.151 ;
     RECT  40.2 2.137 40.32 2.151 ;
     RECT  7.8 2.151 8.112 2.245 ;
     RECT  20.544 0.085 20.568 2.293 ;
     RECT  34.8 2.151 35.112 2.293 ;
     RECT  36.144 2.245 36.168 2.293 ;
     RECT  13.2 2.151 13.512 2.485 ;
     RECT  28.32 2.245 28.344 2.773 ;
     RECT  29.4 2.151 29.712 2.773 ;
     RECT  38.16 2.245 38.184 2.867 ;
     RECT  7.8 2.245 8.232 3.059 ;
     RECT  28.32 2.773 29.712 3.107 ;
     RECT  22.8 2.245 22.824 3.301 ;
     RECT  24 2.151 24.312 3.301 ;
     RECT  16.56 3.301 16.584 3.397 ;
     RECT  18.6 2.151 18.912 3.397 ;
     RECT  22.8 3.301 24.312 3.443 ;
     RECT  27.264 2.677 27.288 3.443 ;
     RECT  15.264 2.245 15.288 3.875 ;
     RECT  16.56 3.397 17.352 4.019 ;
     RECT  29.28 3.107 29.712 4.019 ;
     RECT  5.328 2.245 5.352 4.357 ;
     RECT  5.088 4.357 5.352 4.403 ;
     RECT  23.04 3.443 24.312 4.451 ;
     RECT  30.816 2.821 30.84 4.547 ;
     RECT  12.624 2.485 13.512 4.691 ;
     RECT  18.48 3.397 18.912 4.691 ;
     RECT  34.8 2.293 36.168 4.693 ;
     RECT  5.088 4.403 5.112 4.837 ;
     RECT  6.336 4.453 6.36 4.837 ;
     RECT  7.8 3.059 8.112 4.837 ;
     RECT  17.328 4.019 17.352 5.029 ;
     RECT  29.4 4.019 29.712 5.029 ;
     RECT  17.088 5.029 17.352 5.125 ;
     RECT  10.848 2.245 10.872 5.171 ;
     RECT  20.304 2.293 20.568 5.171 ;
     RECT  34.176 4.693 36.168 5.315 ;
     RECT  4.608 4.837 5.112 5.459 ;
     RECT  38.544 5.029 38.568 5.605 ;
     RECT  23.76 4.451 24.312 5.701 ;
     RECT  16.992 5.125 17.352 5.747 ;
     RECT  20.544 5.171 20.568 6.133 ;
     RECT  28.224 5.365 28.248 6.133 ;
     RECT  26.112 5.029 26.136 6.179 ;
     RECT  13.2 4.691 13.512 6.229 ;
     RECT  23.232 5.701 24.312 6.277 ;
     RECT  20.544 6.133 20.904 6.659 ;
     RECT  27.888 6.133 28.248 6.707 ;
     RECT  6.336 4.837 8.112 6.803 ;
     RECT  38.544 5.605 38.856 6.805 ;
     RECT  23.232 6.277 24.696 7.043 ;
     RECT  23.76 7.043 24.696 7.091 ;
     RECT  6.336 6.803 6.36 7.139 ;
     RECT  16.128 6.805 16.152 7.189 ;
     RECT  17.328 5.747 17.352 7.189 ;
     RECT  18.6 4.691 18.912 7.237 ;
     RECT  20.544 6.659 20.568 7.237 ;
     RECT  12.624 6.229 13.512 7.381 ;
     RECT  21.648 6.805 21.672 7.619 ;
     RECT  34.8 5.315 36.168 7.619 ;
     RECT  31.872 4.261 31.896 7.667 ;
     RECT  27.888 6.707 27.912 7.669 ;
     RECT  29.4 5.029 29.928 7.669 ;
     RECT  26.208 6.805 26.232 7.715 ;
     RECT  4.608 5.459 4.92 7.765 ;
     RECT  27.888 7.669 29.928 7.765 ;
     RECT  7.8 6.803 8.112 7.909 ;
     RECT  3.984 7.765 4.92 7.957 ;
     RECT  12.624 7.381 14.232 7.957 ;
     RECT  38.544 6.805 39.048 8.195 ;
     RECT  32.928 5.269 32.952 8.293 ;
     RECT  27.888 7.765 30.264 8.339 ;
     RECT  9.744 7.141 9.768 8.437 ;
     RECT  3.984 7.957 5.688 8.483 ;
     RECT  6.816 7.909 8.112 8.485 ;
     RECT  16.128 7.189 17.352 8.579 ;
     RECT  16.128 8.579 16.584 8.675 ;
     RECT  38.544 8.195 38.568 8.723 ;
     RECT  18.6 7.237 20.568 8.773 ;
     RECT  18 8.773 20.568 8.819 ;
     RECT  16.56 8.675 16.584 8.867 ;
     RECT  28.704 8.339 30.264 8.963 ;
     RECT  23.76 7.091 24.408 9.109 ;
     RECT  32.928 8.293 33.048 9.155 ;
     RECT  26.496 9.013 26.52 9.397 ;
     RECT  26.208 9.397 26.52 9.443 ;
     RECT  12.528 7.957 14.232 9.637 ;
     RECT  22.896 9.109 24.744 9.683 ;
     RECT  4.608 8.483 5.688 9.731 ;
     RECT  18 8.819 19.08 9.779 ;
     RECT  23.76 9.683 24.744 9.779 ;
     RECT  9.744 8.437 10.296 9.827 ;
     RECT  6.816 8.485 8.232 9.925 ;
     RECT  20.544 8.819 20.568 9.925 ;
     RECT  29.4 8.963 30.264 10.213 ;
     RECT  10.272 9.827 10.296 10.307 ;
     RECT  18 9.779 18.912 10.307 ;
     RECT  12.528 9.637 15.144 10.355 ;
     RECT  28.512 10.213 30.264 10.355 ;
     RECT  4.608 9.731 4.92 10.453 ;
     RECT  13.2 10.355 15.144 10.547 ;
     RECT  6.24 9.925 8.232 10.595 ;
     RECT  28.512 10.355 29.712 10.835 ;
     RECT  26.208 9.443 26.232 10.883 ;
     RECT  3.84 10.453 4.92 10.885 ;
     RECT  6.24 10.595 6.264 10.885 ;
     RECT  3.84 10.885 6.264 10.931 ;
     RECT  3.84 10.931 4.632 11.027 ;
     RECT  20.544 9.925 21.192 11.315 ;
     RECT  34.8 7.619 35.928 11.413 ;
     RECT  40.2 2.151 40.512 11.413 ;
     RECT  5.664 10.931 6.264 11.459 ;
     RECT  32.928 9.155 32.952 11.459 ;
     RECT  7.8 10.595 8.232 11.987 ;
     RECT  13.2 10.547 15.048 12.035 ;
     RECT  23.76 9.779 24.312 12.037 ;
     RECT  39.264 11.413 40.512 12.373 ;
     RECT  20.544 11.315 20.568 12.469 ;
     RECT  5.664 11.459 5.688 12.517 ;
     RECT  13.2 12.035 14.232 12.517 ;
     RECT  29.4 10.835 29.712 12.517 ;
     RECT  34.032 11.413 35.928 12.517 ;
     RECT  20.544 12.469 21.48 12.565 ;
     RECT  23.04 12.037 24.312 12.565 ;
     RECT  7.8 11.987 8.112 12.709 ;
     RECT  34.032 12.517 36.168 12.901 ;
     RECT  2.4 2.151 2.712 13.045 ;
     RECT  20.544 12.565 24.312 13.045 ;
     RECT  28.752 12.517 29.712 13.045 ;
     RECT  13.104 12.517 14.232 13.091 ;
     RECT  20.544 13.045 24.696 13.091 ;
     RECT  30.864 12.517 30.888 13.093 ;
     RECT  38.928 12.373 40.512 13.283 ;
     RECT  38.928 13.283 38.952 13.379 ;
     RECT  4.608 11.027 4.632 13.429 ;
     RECT  5.664 12.517 6.552 13.429 ;
     RECT  2.4 13.045 2.904 13.765 ;
     RECT  30.816 13.093 30.888 13.859 ;
     RECT  34.032 12.901 36.264 14.195 ;
     RECT  4.608 13.429 6.552 14.243 ;
     RECT  23.04 13.091 24.696 14.243 ;
     RECT  4.608 14.243 5.688 14.291 ;
     RECT  30.816 13.859 30.84 14.483 ;
     RECT  18.192 10.307 18.912 14.677 ;
     RECT  15.36 13.669 15.384 14.819 ;
     RECT  23.04 14.243 24.408 14.915 ;
     RECT  18.192 14.677 19.176 14.963 ;
     RECT  7.68 12.709 8.112 15.059 ;
     RECT  37.632 14.149 37.656 15.059 ;
     RECT  10.656 14.197 10.68 15.251 ;
     RECT  2.4 13.765 3.384 15.347 ;
     RECT  4.608 14.291 5.4 15.395 ;
     RECT  28.464 13.045 29.712 15.397 ;
     RECT  4.848 15.395 5.4 15.443 ;
     RECT  34.032 14.195 36.168 15.443 ;
     RECT  34.032 15.443 35.112 15.829 ;
     RECT  23.04 14.915 24.312 15.925 ;
     RECT  2.4 15.347 2.904 16.019 ;
     RECT  4.848 15.443 5.16 16.019 ;
     RECT  20.544 13.091 21.624 16.019 ;
     RECT  28.464 15.397 30.024 16.115 ;
     RECT  13.2 13.091 14.232 16.165 ;
     RECT  25.536 15.397 25.56 16.259 ;
     RECT  12.768 16.165 14.232 16.261 ;
     RECT  33.936 15.829 35.112 16.357 ;
     RECT  28.752 16.115 30.024 16.499 ;
     RECT  36.144 15.443 36.168 16.595 ;
     RECT  18.24 14.963 19.176 17.123 ;
     RECT  18.48 17.123 19.176 17.315 ;
     RECT  26.88 17.077 26.904 17.317 ;
     RECT  26.736 17.317 26.904 17.363 ;
     RECT  33.696 16.357 35.112 17.363 ;
     RECT  12.768 16.261 14.424 17.605 ;
     RECT  20.544 16.019 21.576 17.651 ;
     RECT  12 17.605 14.424 17.699 ;
     RECT  37.632 16.501 37.656 17.843 ;
     RECT  32.448 17.605 32.472 17.891 ;
     RECT  9.6 15.973 9.624 18.133 ;
     RECT  9.12 18.133 9.624 18.179 ;
     RECT  12 17.699 13.512 18.179 ;
     RECT  26.736 17.363 26.76 18.275 ;
     RECT  20.544 17.651 21.48 18.565 ;
     RECT  23.04 15.925 24.408 18.709 ;
     RECT  36.096 18.661 36.12 18.757 ;
     RECT  33.696 17.363 33.72 18.805 ;
     RECT  16.8 17.605 16.824 19.237 ;
     RECT  33.024 18.805 33.72 19.331 ;
     RECT  18.48 17.315 18.912 19.427 ;
     RECT  20.448 18.565 21.48 19.427 ;
     RECT  4.848 16.019 4.872 19.573 ;
     RECT  5.952 18.949 5.976 19.573 ;
     RECT  33.024 19.331 33.24 19.717 ;
     RECT  4.848 19.573 5.976 19.763 ;
     RECT  28.752 16.499 29.712 19.811 ;
     RECT  16.56 19.237 16.824 19.813 ;
     RECT  12.768 18.179 13.512 19.909 ;
     RECT  36.096 18.757 36.216 19.909 ;
     RECT  4.848 19.763 5.688 20.003 ;
     RECT  32.592 19.717 33.24 20.051 ;
     RECT  32.592 20.051 33.048 20.149 ;
     RECT  32.544 20.149 33.048 20.195 ;
     RECT  23.04 18.709 24.552 20.437 ;
     RECT  34.8 17.363 35.112 20.437 ;
     RECT  36.096 19.909 36.84 20.437 ;
     RECT  2.4 16.019 2.712 20.485 ;
     RECT  9.12 18.179 9.144 20.531 ;
     RECT  5.664 20.003 5.688 20.579 ;
     RECT  37.968 18.709 37.992 20.819 ;
     RECT  32.544 20.195 32.616 20.867 ;
     RECT  23.04 20.437 24.888 21.011 ;
     RECT  12.24 19.909 13.512 21.155 ;
     RECT  30.72 19.477 30.744 21.155 ;
     RECT  34.8 20.437 36.84 21.155 ;
     RECT  27.888 20.293 27.912 21.347 ;
     RECT  34.8 21.155 35.88 21.347 ;
     RECT  4.56 20.437 4.584 21.637 ;
     RECT  20.544 19.427 21.48 21.637 ;
     RECT  3.984 21.637 4.584 21.971 ;
     RECT  23.328 21.011 24.552 22.021 ;
     RECT  20.544 21.637 22.2 22.067 ;
     RECT  13.2 21.155 13.512 22.165 ;
     RECT  18.6 19.427 18.912 22.213 ;
     RECT  2.4 20.485 2.808 22.259 ;
     RECT  15.696 19.813 16.824 22.307 ;
     RECT  20.784 22.067 22.2 22.499 ;
     RECT  32.544 20.867 32.568 22.645 ;
     RECT  34.8 21.347 35.496 22.741 ;
     RECT  5.952 21.637 5.976 22.787 ;
     RECT  39.12 19.333 39.144 22.931 ;
     RECT  18.6 22.213 19.032 23.077 ;
     RECT  7.8 15.059 8.112 23.125 ;
     RECT  15.696 22.307 15.72 23.267 ;
     RECT  23.328 22.021 24.744 23.317 ;
     RECT  20.784 22.499 21.48 23.363 ;
     RECT  29.4 19.811 29.712 23.365 ;
     RECT  34.8 22.741 36.36 23.365 ;
     RECT  9.888 22.165 9.912 23.411 ;
     RECT  22.608 23.317 24.984 23.605 ;
     RECT  29.28 23.365 29.712 23.605 ;
     RECT  2.4 22.259 2.712 23.845 ;
     RECT  3.984 21.971 4.008 23.891 ;
     RECT  22.608 23.605 25.416 23.891 ;
     RECT  34.8 23.365 37.224 23.891 ;
     RECT  12.576 22.165 13.512 23.893 ;
     RECT  18.6 23.077 19.368 23.893 ;
     RECT  27.072 22.021 27.096 23.939 ;
     RECT  22.608 23.891 24.984 24.131 ;
     RECT  31.872 22.645 32.568 24.323 ;
     RECT  7.632 23.125 8.112 24.467 ;
     RECT  7.8 24.467 8.112 24.469 ;
     RECT  18.6 23.893 20.136 24.469 ;
     RECT  21.456 23.363 21.48 24.469 ;
     RECT  34.8 23.891 35.112 24.469 ;
     RECT  23.328 24.131 24.984 24.707 ;
     RECT  16.8 22.307 16.824 24.709 ;
     RECT  32.544 24.323 32.568 24.757 ;
     RECT  16.8 24.709 17.064 24.901 ;
     RECT  32.544 24.757 33.096 25.045 ;
     RECT  10.992 23.317 11.016 25.139 ;
     RECT  15.456 23.269 15.576 25.139 ;
     RECT  16.8 24.901 17.112 25.139 ;
     RECT  27.024 24.133 27.048 25.139 ;
     RECT  34.368 24.469 35.112 25.187 ;
     RECT  2.4 23.845 2.808 25.189 ;
     RECT  7.8 24.469 8.232 25.333 ;
     RECT  32.544 25.045 33.192 25.525 ;
     RECT  6.24 24.469 6.264 25.573 ;
     RECT  7.8 25.333 8.328 25.573 ;
     RECT  18.6 24.469 21.48 25.667 ;
     RECT  6.24 25.573 8.328 25.861 ;
     RECT  16.8 25.139 17.064 25.861 ;
     RECT  2.4 25.189 3 25.955 ;
     RECT  36.144 23.891 37.224 26.003 ;
     RECT  29.088 23.605 29.712 26.051 ;
     RECT  15.456 25.139 15.48 26.101 ;
     RECT  16.704 25.861 17.064 26.101 ;
     RECT  15.456 26.101 17.064 26.147 ;
     RECT  6.048 25.861 8.328 26.243 ;
     RECT  15.936 26.147 17.064 26.243 ;
     RECT  27.552 26.101 27.576 26.293 ;
     RECT  6.048 26.243 6.072 26.533 ;
     RECT  12.528 23.893 13.512 26.579 ;
     RECT  18.6 25.667 19.368 26.579 ;
     RECT  34.8 25.187 35.112 26.629 ;
     RECT  36.144 26.003 36.36 26.629 ;
     RECT  7.8 26.243 8.328 26.771 ;
     RECT  27.552 26.293 27.912 26.771 ;
     RECT  32.544 25.525 33.624 26.771 ;
     RECT  32.544 26.771 33.48 26.773 ;
     RECT  34.8 26.629 36.36 26.867 ;
     RECT  34.8 26.867 36.168 26.915 ;
     RECT  38.832 23.701 38.856 27.059 ;
     RECT  29.28 26.051 29.712 27.109 ;
     RECT  15.936 26.243 16.824 27.155 ;
     RECT  5.424 26.533 6.072 27.301 ;
     RECT  7.8 26.771 8.112 27.301 ;
     RECT  15.936 27.155 15.96 27.589 ;
     RECT  23.328 24.707 24.744 27.589 ;
     RECT  5.424 27.301 8.112 27.635 ;
     RECT  27.888 26.771 27.912 27.635 ;
     RECT  34.8 26.915 36.072 27.635 ;
     RECT  15.36 27.589 15.96 27.731 ;
     RECT  23.328 27.589 25.272 27.731 ;
     RECT  23.328 27.731 24.6 27.781 ;
     RECT  22.848 27.781 24.6 27.875 ;
     RECT  13.2 26.579 13.512 27.877 ;
     RECT  29.28 27.109 30.6 27.877 ;
     RECT  31.968 26.773 33.48 27.877 ;
     RECT  34.8 27.635 35.352 27.877 ;
     RECT  18.6 26.579 19.176 27.925 ;
     RECT  3.744 26.725 3.768 27.971 ;
     RECT  10.992 26.149 11.016 27.971 ;
     RECT  21.024 25.667 21.48 28.211 ;
     RECT  6.048 27.635 8.112 28.307 ;
     RECT  13.056 27.877 13.512 28.547 ;
     RECT  31.968 27.877 35.352 28.693 ;
     RECT  6.048 28.307 6.072 28.835 ;
     RECT  17.136 27.877 17.16 28.837 ;
     RECT  17.136 28.837 17.304 28.883 ;
     RECT  12 28.501 12.024 29.123 ;
     RECT  18.6 27.925 19.992 29.123 ;
     RECT  22.848 27.875 24.552 29.123 ;
     RECT  13.2 28.547 13.512 29.125 ;
     RECT  23.04 29.123 24.552 29.173 ;
     RECT  17.184 28.883 17.304 29.269 ;
     RECT  23.04 29.173 25.32 29.315 ;
     RECT  17.184 29.269 17.352 29.555 ;
     RECT  10.848 29.029 10.872 29.651 ;
     RECT  31.92 28.693 35.352 29.795 ;
     RECT  37.056 28.933 37.08 29.795 ;
     RECT  13.2 29.125 13.848 29.893 ;
     RECT  15.936 27.731 15.96 29.893 ;
     RECT  23.04 29.315 24.552 30.035 ;
     RECT  38.16 27.541 38.184 30.035 ;
     RECT  29.088 27.877 30.6 30.085 ;
     RECT  28.896 30.085 30.6 30.277 ;
     RECT  18.6 29.123 19.176 30.373 ;
     RECT  31.92 29.795 35.112 30.611 ;
     RECT  7.392 28.307 8.112 30.661 ;
     RECT  26.736 30.037 26.76 30.661 ;
     RECT  21.264 28.211 21.48 30.709 ;
     RECT  17.184 29.555 17.208 30.755 ;
     RECT  21.12 30.709 21.48 30.755 ;
     RECT  15.552 29.893 15.96 30.803 ;
     RECT  26.736 30.661 26.856 30.803 ;
     RECT  23.04 30.035 24.312 30.805 ;
     RECT  7.392 30.661 8.616 30.899 ;
     RECT  21.12 30.755 21.144 30.899 ;
     RECT  7.8 30.899 8.616 31.283 ;
     RECT  32.112 30.611 35.112 31.331 ;
     RECT  10.464 31.237 10.824 31.379 ;
     RECT  15.552 30.803 15.576 31.379 ;
     RECT  33.84 31.331 35.112 31.571 ;
     RECT  22.224 30.805 24.312 31.667 ;
     RECT  28.896 30.277 30.696 31.765 ;
     RECT  34.128 31.571 35.112 31.765 ;
     RECT  28.896 31.765 30.744 31.955 ;
     RECT  38.016 30.949 38.04 31.955 ;
     RECT  13.2 29.893 14.088 32.051 ;
     RECT  29.4 31.955 30.744 32.389 ;
     RECT  32.112 31.331 32.664 32.483 ;
     RECT  10.464 31.379 10.488 32.723 ;
     RECT  29.4 32.389 30.936 32.773 ;
     RECT  29.4 32.773 31.416 32.819 ;
     RECT  34.128 31.765 35.208 32.819 ;
     RECT  7.8 31.283 8.112 33.013 ;
     RECT  30.912 32.819 31.416 33.539 ;
     RECT  27.936 32.437 27.96 33.683 ;
     RECT  5.28 30.709 5.304 34.067 ;
     RECT  22.752 31.667 24.312 34.117 ;
     RECT  37.44 33.541 37.464 34.117 ;
     RECT  13.2 32.051 13.608 34.165 ;
     RECT  18.6 30.373 19.368 34.165 ;
     RECT  6.864 33.013 8.112 34.355 ;
     RECT  13.104 34.165 13.608 34.357 ;
     RECT  3.984 32.053 4.008 34.403 ;
     RECT  22.752 34.117 24.552 34.403 ;
     RECT  34.128 32.819 35.112 34.499 ;
     RECT  37.44 34.117 37.656 34.501 ;
     RECT  22.752 34.403 24.312 34.691 ;
     RECT  31.392 33.539 31.416 34.741 ;
     RECT  31.296 34.741 31.416 34.789 ;
     RECT  32.448 32.483 32.664 34.789 ;
     RECT  22.752 34.691 22.776 34.835 ;
     RECT  31.296 34.789 32.664 34.933 ;
     RECT  30.816 34.933 32.664 34.979 ;
     RECT  7.056 34.355 8.112 35.171 ;
     RECT  36.912 34.501 37.656 35.171 ;
     RECT  18.192 34.165 19.368 35.363 ;
     RECT  39.024 32.341 39.048 35.363 ;
     RECT  11.424 34.597 11.448 35.459 ;
     RECT  27.312 35.317 27.336 35.845 ;
     RECT  20.448 33.925 20.472 35.939 ;
     RECT  29.4 32.819 29.832 36.085 ;
     RECT  30.816 34.979 30.84 36.085 ;
     RECT  33.648 34.741 33.672 36.131 ;
     RECT  27.312 35.845 28.152 36.275 ;
     RECT  36.912 35.171 36.936 36.325 ;
     RECT  5.616 35.605 5.64 36.467 ;
     RECT  13.104 34.357 14.328 36.515 ;
     RECT  18.192 35.363 19.176 36.517 ;
     RECT  13.104 36.515 13.512 36.947 ;
     RECT  40.2 13.283 40.512 36.997 ;
     RECT  31.92 34.979 32.664 37.045 ;
     RECT  31.92 37.045 33.576 37.187 ;
     RECT  34.8 34.499 35.112 37.381 ;
     RECT  29.4 36.085 30.84 37.427 ;
     RECT  31.92 37.187 31.992 37.429 ;
     RECT  31.632 37.429 31.992 37.475 ;
     RECT  13.2 36.947 13.512 37.573 ;
     RECT  18.192 36.517 19.704 37.619 ;
     RECT  2.4 25.955 2.712 37.621 ;
     RECT  34.8 37.381 35.544 37.859 ;
     RECT  28.128 36.275 28.152 37.861 ;
     RECT  29.4 37.427 30.216 37.861 ;
     RECT  36.912 36.325 37.848 38.003 ;
     RECT  33.024 37.187 33.576 38.099 ;
     RECT  39.936 36.997 40.512 38.149 ;
     RECT  5.424 36.661 5.448 38.243 ;
     RECT  13.2 37.573 14.088 38.435 ;
     RECT  28.128 37.861 30.216 38.435 ;
     RECT  37.056 38.003 37.848 38.675 ;
     RECT  18.192 37.619 19.176 38.819 ;
     RECT  22.752 36.421 22.776 38.819 ;
     RECT  37.056 38.675 37.224 39.011 ;
     RECT  28.128 38.435 29.832 39.013 ;
     RECT  33.024 38.099 33.048 39.299 ;
     RECT  37.2 39.011 37.224 39.299 ;
     RECT  6 38.773 6.024 39.347 ;
     RECT  15.984 37.429 16.008 39.347 ;
     RECT  28.032 39.013 29.832 39.539 ;
     RECT  7.68 35.171 8.112 39.779 ;
     RECT  18.6 38.819 19.176 39.877 ;
     RECT  28.032 39.539 29.712 39.923 ;
     RECT  31.632 37.475 31.656 39.923 ;
     RECT  2.4 37.621 3.096 40.307 ;
     RECT  39.312 38.149 40.512 40.403 ;
     RECT  18.6 39.877 19.656 40.595 ;
     RECT  28.032 39.923 28.056 40.643 ;
     RECT  10.272 37.573 10.296 40.835 ;
     RECT  33.072 39.589 33.096 40.883 ;
     RECT  2.4 40.307 2.712 41.049 ;
     RECT  7.8 39.779 8.112 41.049 ;
     RECT  13.2 38.435 13.512 41.049 ;
     RECT  18.6 40.595 18.912 41.049 ;
     RECT  24 34.691 24.312 41.049 ;
     RECT  29.4 39.923 29.712 41.049 ;
     RECT  34.8 37.859 35.112 41.049 ;
     RECT  40.2 40.403 40.512 41.049 ;
     RECT  2.4 41.049 2.52 41.063 ;
     RECT  7.8 41.049 7.92 41.063 ;
     RECT  13.2 41.049 13.32 41.063 ;
     RECT  18.6 41.049 18.72 41.063 ;
     RECT  24 41.049 24.12 41.063 ;
     RECT  29.4 41.049 29.52 41.063 ;
     RECT  34.8 41.049 34.92 41.063 ;
     RECT  40.2 41.049 40.32 41.063 ;
  END
END ot_s81sl_cap_ld
END LIBRARY
